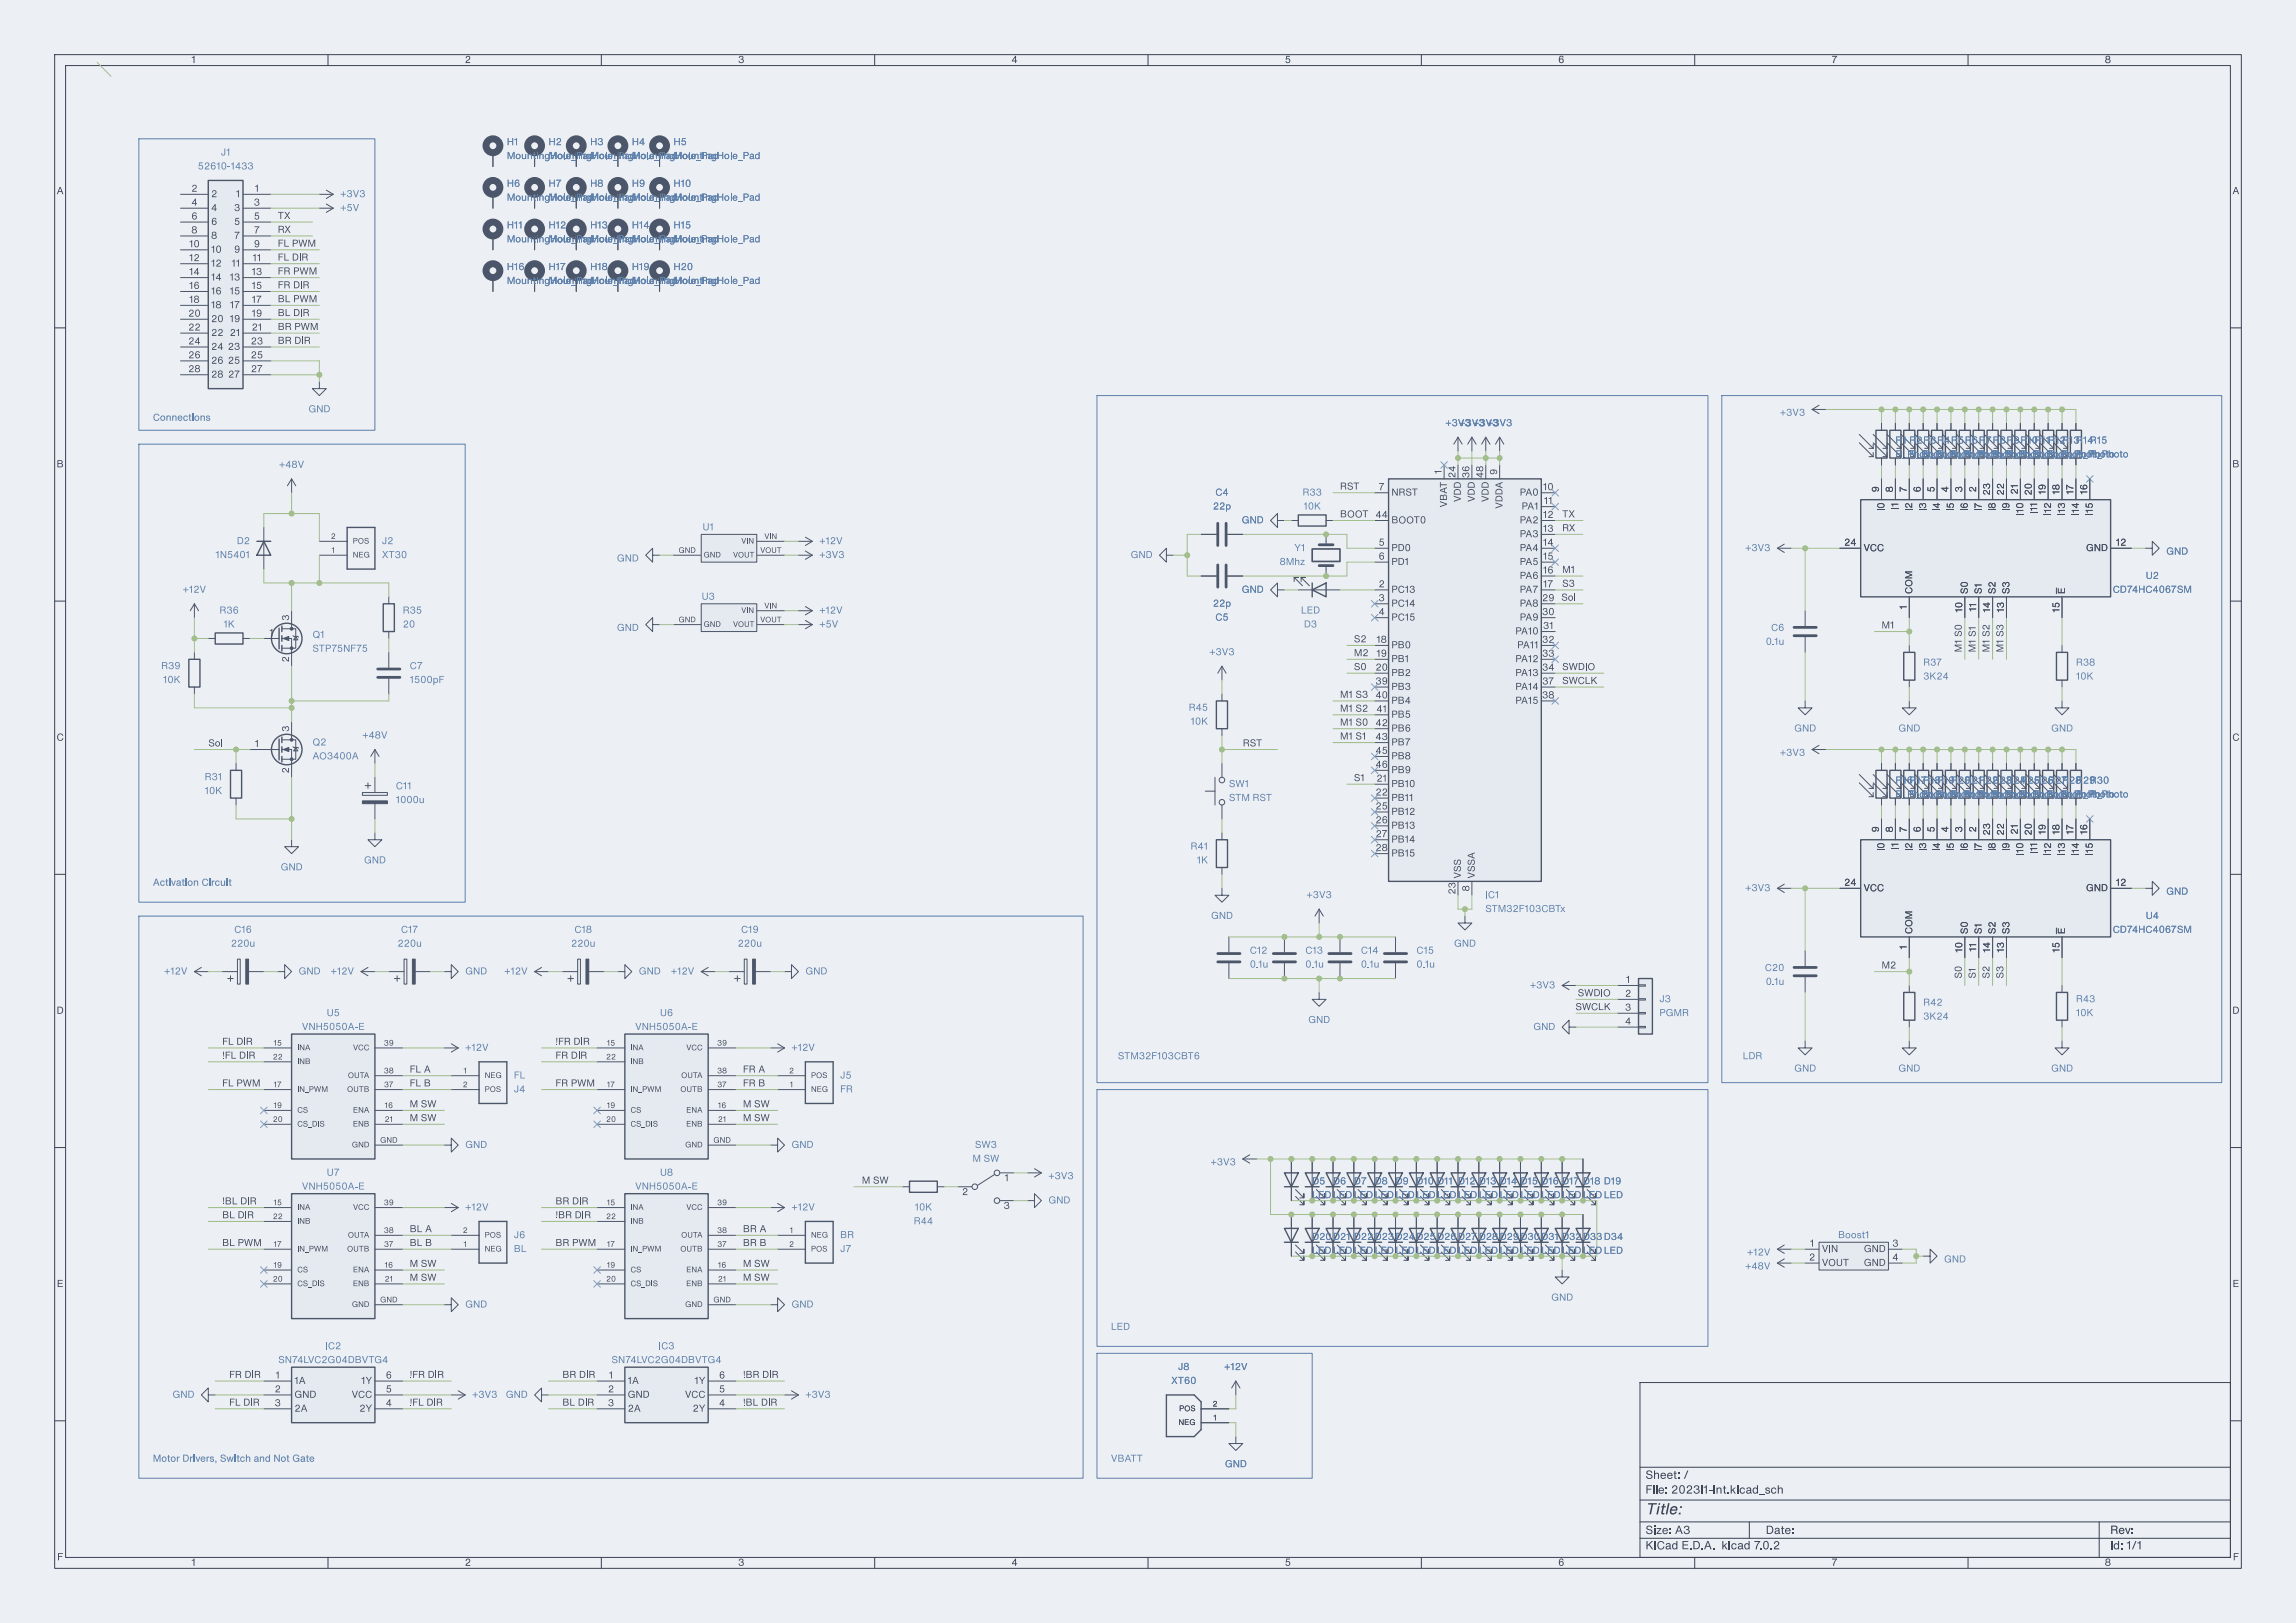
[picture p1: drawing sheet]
<svg xmlns="http://www.w3.org/2000/svg" width="420mm" height="297mm" viewBox="0 0 420 297" stroke-linecap="round" stroke-linejoin="round" font-family="sans-serif">
<defs><g id="words">
<text font-size="2.8" fill="#3b4252" x="301" y="277.8">Title:</text>
<g font-size="2.1" fill="#3b4252">
<text x="301" y="273.8">File: 2023l1-int.kicad_sch</text>
<text x="301" y="271.1">Sheet: /</text>
<text x="301" y="281.2">Size: A3</text>
<text x="323" y="281.2">Date:</text>
<text x="386" y="281.2">Rev:</text>
<text x="301" y="284">KiCad E.D.A. kicad 7.0.2</text>
<text x="386" y="284">Id: 1/1</text>
</g>
<g font-size="1.8" fill="#3b4252">
<text x="35" y="12">1</text>
<text x="85" y="12">2</text>
<text x="135" y="12">3</text>
<text x="185" y="12">4</text>
<text x="235" y="12">5</text>
<text x="285" y="12">6</text>
<text x="335" y="12">7</text>
<text x="385" y="12">8</text>
<text x="10.3" y="36">A</text>
<text x="408.3" y="36">A</text>
<text x="10.3" y="86">B</text>
<text x="408.3" y="86">B</text>
<text x="10.3" y="136">C</text>
<text x="408.3" y="136">C</text>
<text x="10.4" y="186">D</text>
<text x="408.3" y="186">D</text>
<text x="10.4" y="236">E</text>
<text x="408.4" y="236">E</text>
<text x="10.5" y="286">F</text>
<text x="35" y="287">1</text>
<text x="85" y="287">2</text>
<text x="135" y="287">3</text>
<text x="185" y="287">4</text>
<text x="235" y="287">5</text>
<text x="285" y="287">6</text>
<text x="335" y="287">7</text>
<text x="385" y="287">8</text>
<text x="408.4" y="286">F</text>
</g>
<g font-size="1.8" fill="#5e81ac">
<text x="40.4" y="28.9">J1</text>
<text x="92.7" y="27">H1</text>
<text x="92.7" y="29.5">MountingHole_PadMountingHole_PadMountingHole_Pad</text>
<text x="100.3" y="27">H2</text>
<text x="107.9" y="27">H3</text>
<text x="115.6" y="27">H4</text>
<text x="123.2" y="27">H5</text>
<text x="36.2" y="31.4">52610-1433</text>
<text x="92.7" y="34.6">H6</text>
<text x="100.3" y="34.6">H7</text>
<text x="107.9" y="34.6">H8</text>
<text x="115.6" y="34.6">H9</text>
<text x="123.2" y="34.6">H10</text>
<text x="62.2" y="36.5">+3V3</text>
<text x="62.2" y="39">+5V</text>
<text x="92.7" y="37.1">MountingHole_PadMountingHole_PadMountingHole_Pad</text>
<text x="92.7" y="42.2">H11</text>
<text x="100.3" y="42.2">H12</text>
<text x="107.9" y="42.2">H13</text>
<text x="115.6" y="42.2">H14</text>
<text x="123.2" y="42.2">H15</text>
<text x="92.7" y="49.8">H16</text>
<text x="92.7" y="52.4">MountingHole_PadMountingHole_PadMountingHole_Pad</text>
<text x="100.3" y="49.8">H17</text>
<text x="100.3" y="52.4">MountingHole_PadMountingHole_Pad</text>
<text x="107.9" y="49.8">H18</text>
<text x="115.6" y="49.8">H19</text>
<text x="123.2" y="49.8">H20</text>
<text x="27.9" y="77.2">Connections</text>
<text x="56.4" y="75.9">GND</text>
<text x="325.6" y="76.5">+3V3</text>
<text x="264.4" y="78.4">+3V3 +3V3</text>
<text x="346.7" y="81.6">R1R2R3R4R5R6R7R8R9R10R11R12R13R14R15</text>
<text x="51" y="86">+48V</text>
<text x="346.7" y="84.1">R_Photo</text>
<text x="349.2" y="84.1">R_Photo R_Photo</text>
<text x="351.8" y="84.1">R_Photo R_Photo R_Photo R_Photo R_Photo</text>
<text x="351.8" y="84.1">R_Photo</text>
<text x="369.6" y="84.1">R_Photo</text>
<text x="372.1" y="84.1">R_Photo</text>
<text x="374.6" y="84.1">R_Photo R_Photo</text>
<text x="221.8" y="93.7">22p</text>
<text x="222.3" y="91.1">C4</text>
<text x="238.3" y="91.1">R33</text>
<text x="238.4" y="93.7">10K</text>
<text x="43.3" y="100">D2</text>
<text x="69.8" y="100">J2</text>
<text x="128.5" y="97.5">U1</text>
<text x="149.9" y="100">+12V</text>
<text x="227.1" y="96.2">GND</text>
<text x="236.7" y="101.3">Y1</text>
<text x="319.2" y="101.3">+3V3</text>
<text x="396.2" y="101.9">GND</text>
<text x="39.4" y="102.5">1N5401</text>
<text x="69.8" y="102.5">XT30</text>
<text x="112.8" y="103.2">GND</text>
<text x="149.9" y="102.5">+3V3</text>
<text x="206.8" y="102.5">GND</text>
<text x="234.1" y="103.8">8Mhz</text>
<text x="392.5" y="106.4">U2</text>
<text x="33.4" y="108.9">+12V</text>
<text x="40.1" y="112.7">R36</text>
<text x="73.7" y="112.7">R35</text>
<text x="128.3" y="110.2">U3</text>
<text x="149.9" y="112.7">+12V</text>
<text x="221.8" y="111.4">22p</text>
<text x="222.3" y="114">C5</text>
<text x="227.1" y="108.9">GND</text>
<text x="238" y="112.7">LED</text>
<text x="386.5" y="108.9">CD74HC4067SM</text>
<text x="40.9" y="115.2">1K</text>
<text x="57.1" y="117.2">Q1</text>
<text x="57.1" y="119.7">STP75NF75</text>
<text x="73.7" y="115.2">20</text>
<text x="112.8" y="115.9">GND</text>
<text x="149.9" y="115.2">+5V</text>
<text x="238.5" y="115.2">D3</text>
<text x="323" y="118.4">0.1u</text>
<text x="324" y="115.9">C6</text>
<text x="29.5" y="122.9">R39</text>
<text x="29.8" y="125.4">10K</text>
<text x="74.9" y="122.9">C7</text>
<text x="74.9" y="125.4">1500pF</text>
<text x="221.2" y="120.3">+3V3</text>
<text x="351.8" y="122.2">R37</text>
<text x="351.8" y="124.8">3K24</text>
<text x="379.7" y="122.2">R38</text>
<text x="379.7" y="124.8">10K</text>
<text x="217.4" y="130.5">R45</text>
<text x="57.1" y="136.8">Q2</text>
<text x="66.3" y="135.6">+48V</text>
<text x="217.8" y="133">10K</text>
<text x="328.2" y="134.3">GND</text>
<text x="347.2" y="134.3">GND</text>
<text x="375.2" y="134.3">GND</text>
<text x="37.4" y="143.2">R31</text>
<text x="57.1" y="139.4">AO3400A</text>
<text x="325.6" y="138.7">+3V3</text>
<text x="346.7" y="143.8">R16R17R18R19R20R21R22R23R24R25R26R27R28R29R30</text>
<text x="37.4" y="145.7">10K</text>
<text x="72.4" y="144.8">C11</text>
<text x="72.4" y="147.4">1000u</text>
<text x="224.8" y="144.5">SW1</text>
<text x="224.8" y="147">STM RST</text>
<text x="346.7" y="146.4">R_Photo R_Photo</text>
<text x="359.4" y="146.4">R_Photo R_Photo R_Photo R_Photo</text>
<text x="217.8" y="155.9">R41</text>
<text x="51.3" y="159.7">GND</text>
<text x="66.6" y="158.4">GND</text>
<text x="218.9" y="158.4">1K</text>
<text x="27.9" y="162.3">Activation Circuit</text>
<text x="239" y="164.8">+3V3</text>
<text x="271.7" y="164.8">IC1</text>
<text x="271.7" y="167.3">STM32F103CBTx</text>
<text x="319.2" y="163.5">+3V3</text>
<text x="396.2" y="164.1">GND</text>
<text x="42.2" y="173.7">220u</text>
<text x="42.8" y="171.1">C16</text>
<text x="72.7" y="173.7">220u</text>
<text x="73.3" y="171.1">C17</text>
<text x="104.4" y="173.7">220u</text>
<text x="105.1" y="171.1">C18</text>
<text x="134.9" y="173.7">220u</text>
<text x="135.5" y="171.1">C19</text>
<text x="221.5" y="168.6">GND</text>
<text x="266" y="173.7">GND</text>
<text x="386.5" y="171.1">CD74HC4067SM</text>
<text x="392.5" y="168.6">U4</text>
<text x="30" y="178.7">+12V</text>
<text x="54.6" y="178.7">GND</text>
<text x="60.5" y="178.7">+12V</text>
<text x="85.1" y="178.7">GND</text>
<text x="92.2" y="178.7">+12V</text>
<text x="116.8" y="178.7">GND</text>
<text x="122.7" y="178.7">+12V</text>
<text x="147.3" y="178.7">GND</text>
<text x="228.6" y="174.9">C12</text>
<text x="228.6" y="177.5">0.1u</text>
<text x="238.8" y="174.9">C13</text>
<text x="238.8" y="177.5">0.1u</text>
<text x="248.9" y="174.9">C14</text>
<text x="248.9" y="177.5">0.1u</text>
<text x="259.1" y="174.9">C15</text>
<text x="259.1" y="177.5">0.1u</text>
<text x="322.8" y="178.1">C20</text>
<text x="279.9" y="181.3">+3V3</text>
<text x="303.5" y="183.8">J3</text>
<text x="323" y="180.7">0.1u</text>
<text x="351.8" y="184.5">R42</text>
<text x="379.7" y="183.8">R43</text>
<text x="55.2" y="188.9">VNH5050A-E</text>
<text x="59.8" y="186.4">U5</text>
<text x="116.2" y="188.9">VNH5050A-E</text>
<text x="120.7" y="186.4">U6</text>
<text x="239.3" y="187.6">GND</text>
<text x="280.5" y="188.9">GND</text>
<text x="303.5" y="186.4">PGMR</text>
<text x="351.8" y="187">3K24</text>
<text x="379.7" y="186.4">10K</text>
<text x="85.1" y="192.7">+12V</text>
<text x="94" y="197.8">FL</text>
<text x="144.8" y="192.7">+12V</text>
<text x="153.7" y="197.8">J5</text>
<text x="204.5" y="194.1">STM32F103CBT6</text>
<text x="318.8" y="194.1">LDR</text>
<text x="328.2" y="196.5">GND</text>
<text x="347.2" y="196.5">GND</text>
<text x="375.2" y="196.5">GND</text>
<text x="94" y="200.3">J4</text>
<text x="153.7" y="200.3">FR</text>
<text x="59.8" y="215.6">U7</text>
<text x="85.1" y="210.5">GND</text>
<text x="120.7" y="215.6">U8</text>
<text x="144.8" y="210.5">GND</text>
<text x="177.9" y="213">M SW</text>
<text x="178.3" y="210.5">SW3</text>
<text x="221.4" y="213.7">+3V3</text>
<text x="55.2" y="218.1">VNH5050A-E</text>
<text x="85.1" y="221.9">+12V</text>
<text x="116.2" y="218.1">VNH5050A-E</text>
<text x="144.8" y="221.9">+12V</text>
<text x="167.3" y="221.9">10K</text>
<text x="191.8" y="216.2">+3V3</text>
<text x="191.8" y="220.7">GND</text>
<text x="240" y="217.2">D5</text>
<text x="243.8" y="217.2">D6</text>
<text x="247.6" y="217.2">D7</text>
<text x="251.5" y="217.2">D8</text>
<text x="255.3" y="217.2">D9</text>
<text x="259.1" y="217.2">D10</text>
<text x="262.9" y="217.2">D11</text>
<text x="266.7" y="217.2">D12</text>
<text x="270.5" y="217.2">D13 D14 D15</text>
<text x="281.9" y="217.2">D16</text>
<text x="285.8" y="217.2">D17</text>
<text x="289.6" y="217.2">D18 D19</text>
<text x="94" y="227">J6</text>
<text x="153.7" y="227">BR</text>
<text x="167.1" y="224.5">R44</text>
<text x="240" y="227.3">D20</text>
<text x="243.8" y="227.3">D21</text>
<text x="247.6" y="227.3">D22</text>
<text x="251.5" y="227.3">D23 D24 D25</text>
<text x="262.9" y="227.3">D26</text>
<text x="266.7" y="227.3">D27</text>
<text x="270.5" y="227.3">D28 D29 D30</text>
<text x="281.9" y="227.3">D31</text>
<text x="285.8" y="227.3">D32</text>
<text x="289.6" y="227.3">D33 D34</text>
<text x="336.2" y="227">Boost1</text>
<text x="94" y="229.5">BL</text>
<text x="153.7" y="229.5">J7</text>
<text x="319.2" y="232.7">+48V</text>
<text x="319.6" y="230.2">+12V</text>
<text x="355.6" y="231.5">GND</text>
<text x="85.1" y="239.7">GND</text>
<text x="144.8" y="239.7">GND</text>
<text x="283.7" y="238.4">GND</text>
<text x="203.2" y="243.6">LED</text>
<text x="50.9" y="249.9">SN74LVC2G04DBVTG4</text>
<text x="59.5" y="247.3">IC2</text>
<text x="111.9" y="249.9">SN74LVC2G04DBVTG4</text>
<text x="120.5" y="247.3">IC3</text>
<text x="215.5" y="251.1">J8</text>
<text x="223.9" y="251.1">+12V</text>
<text x="31.6" y="256.2">GND</text>
<text x="86.4" y="256.2">+3V3</text>
<text x="92.5" y="256.2">GND</text>
<text x="147.3" y="256.2">+3V3</text>
<text x="214.2" y="253.7">XT60</text>
<text x="27.9" y="267.7">Motor Drivers,Switch and Not Gate</text>
<text x="203.2" y="267.7">VBATT</text>
<text x="224.1" y="268.9">GND</text>
</g>
<g font-size="1.8" fill="#4c566a">
<text x="100.3" y="29.5">MountingHole_PadMountingHole_Pad</text>
<text x="100.3" y="37.1">MountingHole_PadMountingHole_Pad</text>
<text x="92.7" y="44.8">MountingHole_PadMountingHole_PadMountingHole_Pad</text>
<text x="100.3" y="44.8">MountingHole_PadMountingHole_Pad</text>
</g>
<g font-size="1.8" fill="#434c5e">
<text x="35" y="35.3">2</text>
<text x="46.6" y="35.3">1</text>
<text x="35" y="37.8">4</text>
<text x="35" y="40.4">6</text>
<text x="38.6" y="36.5">2</text>
<text x="38.6" y="39">4</text>
<text x="38.6" y="41.6">6</text>
<text x="42.8" y="39">3</text>
<text x="42.8" y="41.6">5</text>
<text x="43.1" y="36.5">1</text>
<text x="46.4" y="37.8">3</text>
<text x="46.4" y="40.4">5</text>
<text x="50.8" y="40.3">TX</text>
<text x="34.6" y="45.5">10</text>
<text x="35" y="42.9">8</text>
<text x="38.6" y="46.7">10</text>
<text x="38.6" y="44.1">8</text>
<text x="42.8" y="44.1">7</text>
<text x="42.8" y="46.7">9</text>
<text x="46.4" y="42.9">7</text>
<text x="46.4" y="45.5">9</text>
<text x="50.8" y="45.4">FL PWM</text>
<text x="50.8" y="42.8">RX</text>
<text x="50.8" y="47.9">FL DIR</text>
<text x="34.6" y="48">12</text>
<text x="34.6" y="50.5">14</text>
<text x="34.6" y="53.1">16</text>
<text x="38.6" y="49.2">12</text>
<text x="38.6" y="51.7">14</text>
<text x="42" y="51.7">13</text>
<text x="42.3" y="49.2">11</text>
<text x="46" y="50.5">13</text>
<text x="46" y="53.1">15</text>
<text x="46.2" y="48">11</text>
<text x="50.8" y="53">FR DIR</text>
<text x="50.8" y="50.5">FR PWM</text>
<text x="34.4" y="58.2">20</text>
<text x="34.6" y="55.6">18</text>
<text x="38.6" y="54.3">16</text>
<text x="38.6" y="56.8">18</text>
<text x="38.6" y="59.4">20</text>
<text x="42" y="54.3">15</text>
<text x="42" y="59.4">19</text>
<text x="42" y="56.8">17</text>
<text x="46" y="58.2">19</text>
<text x="46" y="55.6">17</text>
<text x="50.8" y="58.1">BL DIR</text>
<text x="50.8" y="55.5">BL PWM</text>
<text x="34.4" y="60.7">22</text>
<text x="34.4" y="63.2">24</text>
<text x="34.4" y="65.8">26</text>
<text x="38.6" y="61.9">22</text>
<text x="38.6" y="64.4">24</text>
<text x="41.7" y="64.4">23</text>
<text x="42" y="61.9">21</text>
<text x="45.9" y="63.2">23</text>
<text x="45.9" y="65.8">25</text>
<text x="46" y="60.7">21</text>
<text x="50.8" y="63.2">BR DIR</text>
<text x="50.8" y="60.6">BR PWM</text>
<text x="34.4" y="68.3">28</text>
<text x="38.6" y="67">26</text>
<text x="38.6" y="69.5">28</text>
<text x="41.7" y="67">25</text>
<text x="41.7" y="69.5">27</text>
<text x="45.9" y="68.3">27</text>
<text x="245.1" y="89.8">RST</text>
<text x="252.2" y="89.9">7</text>
<text x="263.9" y="86.8" transform="rotate(-90 263.9 86.8)">1</text>
<text x="266.4" y="87.5" transform="rotate(-90 266.4 87.5)">24</text>
<text x="269" y="87.5" transform="rotate(-90 269 87.5)">36</text>
<text x="271.5" y="87.5" transform="rotate(-90 271.5 87.5)">48</text>
<text x="274.1" y="86.9" transform="rotate(-90 274.1 86.9)">9</text>
<text x="282.2" y="89.9">10</text>
<text x="245.1" y="94.9">BOOT</text>
<text x="251.6" y="95">44</text>
<text x="254.5" y="91.1">NRST</text>
<text x="265.1" y="92.9" transform="rotate(-90 265.1 92.9)">VBAT</text>
<text x="267.6" y="91.9" transform="rotate(-90 267.6 91.9)">VDD</text>
<text x="270.2" y="91.9" transform="rotate(-90 270.2 91.9)">VDD</text>
<text x="272.7" y="91.9" transform="rotate(-90 272.7 91.9)">VDD</text>
<text x="275.3" y="93.1" transform="rotate(-90 275.3 93.1)">VDDA</text>
<text x="278" y="91.1">PA0</text>
<text x="278.3" y="93.7">PA1</text>
<text x="282.2" y="95">12</text>
<text x="282.4" y="92.5">11</text>
<text x="285.8" y="94.9">TX</text>
<text x="343.9" y="90.1" transform="rotate(-90 343.9 90.1)">9</text>
<text x="345.1" y="93.6" transform="rotate(-90 345.1 93.6)">I0</text>
<text x="346.5" y="90.1" transform="rotate(-90 346.5 90.1)">8</text>
<text x="347.7" y="93.2" transform="rotate(-90 347.7 93.2)">I1</text>
<text x="349" y="90.1" transform="rotate(-90 349 90.1)">7</text>
<text x="350.2" y="93.6" transform="rotate(-90 350.2 93.6)">I2</text>
<text x="351.5" y="90.1" transform="rotate(-90 351.5 90.1)">6</text>
<text x="352.7" y="93.6" transform="rotate(-90 352.7 93.6)">I3</text>
<text x="354.1" y="90.1" transform="rotate(-90 354.1 90.1)">5</text>
<text x="355.3" y="93.6" transform="rotate(-90 355.3 93.6)">I4</text>
<text x="356.6" y="90.1" transform="rotate(-90 356.6 90.1)">4</text>
<text x="357.8" y="93.6" transform="rotate(-90 357.8 93.6)">I5</text>
<text x="359.2" y="90.1" transform="rotate(-90 359.2 90.1)">3</text>
<text x="360.4" y="93.6" transform="rotate(-90 360.4 93.6)">I6</text>
<text x="361.7" y="90.1" transform="rotate(-90 361.7 90.1)">2</text>
<text x="362.9" y="93.6" transform="rotate(-90 362.9 93.6)">I7</text>
<text x="364.2" y="90.7" transform="rotate(-90 364.2 90.7)">23</text>
<text x="365.4" y="93.6" transform="rotate(-90 365.4 93.6)">I8</text>
<text x="366.8" y="90.7" transform="rotate(-90 366.8 90.7)">22</text>
<text x="368" y="93.6" transform="rotate(-90 368 93.6)">I9</text>
<text x="369.3" y="90.5" transform="rotate(-90 369.3 90.5)">21</text>
<text x="370.5" y="94.4" transform="rotate(-90 370.5 94.4)">I10</text>
<text x="371.9" y="90.7" transform="rotate(-90 371.9 90.7)">20</text>
<text x="373.1" y="94" transform="rotate(-90 373.1 94)">I11</text>
<text x="374.4" y="90.5" transform="rotate(-90 374.4 90.5)">19</text>
<text x="375.6" y="94.4" transform="rotate(-90 375.6 94.4)">I12</text>
<text x="376.9" y="90.5" transform="rotate(-90 376.9 90.5)">18</text>
<text x="378.1" y="94.4" transform="rotate(-90 378.1 94.4)">I13</text>
<text x="379.5" y="90.5" transform="rotate(-90 379.5 90.5)">17</text>
<text x="380.7" y="94.4" transform="rotate(-90 380.7 94.4)">I14</text>
<text x="382" y="90.5" transform="rotate(-90 382 90.5)">16</text>
<text x="383.2" y="94.4" transform="rotate(-90 383.2 94.4)">I15</text>
<text x="252.2" y="100.1">5</text>
<text x="254.5" y="96.2">BOOT0</text>
<text x="254.5" y="101.3">PD0</text>
<text x="278" y="96.2">PA2</text>
<text x="278" y="98.7">PA3</text>
<text x="278" y="101.3">PA4</text>
<text x="282.2" y="97.5">13</text>
<text x="282.2" y="100.1">14</text>
<text x="285.8" y="97.4">RX</text>
<text x="337.3" y="100.1">24</text>
<text x="340.9" y="101.3">VCC</text>
<text x="381.6" y="101.3">GND</text>
<text x="387" y="100.1">12</text>
<text x="252.2" y="107.7">2</text>
<text x="252.2" y="102.6">6</text>
<text x="254.5" y="103.8">PD1</text>
<text x="278" y="103.8">PA5</text>
<text x="278" y="106.4">PA6</text>
<text x="282.2" y="102.6">15</text>
<text x="282.2" y="105.2">16</text>
<text x="282.3" y="107.7">17</text>
<text x="285.8" y="107.6">S3</text>
<text x="285.8" y="105.1">M1</text>
<text x="53.1" y="113.6" transform="rotate(-90 53.1 113.6)">3</text>
<text x="252.2" y="110.2">3</text>
<text x="252.2" y="112.8">4</text>
<text x="254.5" y="108.9">PC13</text>
<text x="254.5" y="111.4">PC14</text>
<text x="254.5" y="114">PC15</text>
<text x="278" y="108.9">PA7</text>
<text x="278" y="111.4">PA8</text>
<text x="278" y="114">PA9</text>
<text x="282.1" y="110.2">29</text>
<text x="282.1" y="112.8">30</text>
<text x="285.6" y="110.1">Sol</text>
<text x="349" y="111.5" transform="rotate(-90 349 111.5)">1</text>
<text x="350.2" y="108.7" transform="rotate(-90 350.2 108.7)">COM</text>
<text x="359.2" y="112.1" transform="rotate(-90 359.2 112.1)">10</text>
<text x="360.4" y="108.7" transform="rotate(-90 360.4 108.7)">S0</text>
<text x="361.7" y="111.9" transform="rotate(-90 361.7 111.9)">11</text>
<text x="362.9" y="108.7" transform="rotate(-90 362.9 108.7)">S1</text>
<text x="364.2" y="112.1" transform="rotate(-90 364.2 112.1)">14</text>
<text x="365.4" y="108.7" transform="rotate(-90 365.4 108.7)">S2</text>
<text x="366.8" y="112.1" transform="rotate(-90 366.8 112.1)">13</text>
<text x="368" y="108.7" transform="rotate(-90 368 108.7)">S3</text>
<text x="376.9" y="112.1" transform="rotate(-90 376.9 112.1)">15</text>
<text x="49.3" y="116.6">1</text>
<text x="247.6" y="117.8">S2</text>
<text x="251.8" y="117.9">18</text>
<text x="254.5" y="119.1">PB0</text>
<text x="277.2" y="116.5">PA10</text>
<text x="277.5" y="119.1">PA11</text>
<text x="282.1" y="117.9">32</text>
<text x="282.2" y="115.3">31</text>
<text x="344.2" y="115.2">M1</text>
<text x="359.1" y="119.4" transform="rotate(-90 359.1 119.4)">M1 S0</text>
<text x="361.6" y="119.4" transform="rotate(-90 361.6 119.4)">M1 S1</text>
<text x="364.1" y="119.4" transform="rotate(-90 364.1 119.4)">M1 S2</text>
<text x="366.7" y="119.4" transform="rotate(-90 366.7 119.4)">M1 S3</text>
<text x="53.1" y="121.2" transform="rotate(-90 53.1 121.2)">2</text>
<text x="247.6" y="122.8">S0</text>
<text x="247.6" y="120.3">M2</text>
<text x="251.6" y="122.9">20</text>
<text x="251.6" y="125.5">39</text>
<text x="251.8" y="120.4">19</text>
<text x="254.5" y="121.6">PB1</text>
<text x="254.5" y="124.1">PB2</text>
<text x="277.2" y="121.6">PA12</text>
<text x="277.2" y="124.1">PA13</text>
<text x="282.1" y="120.4">33</text>
<text x="282.1" y="122.9">34</text>
<text x="282.1" y="125.5">37</text>
<text x="285.8" y="125.4">SWCLK</text>
<text x="285.8" y="122.8">SWDIO</text>
<text x="245.1" y="130.5">M1 S2</text>
<text x="245.1" y="127.9">M1 S3</text>
<text x="251.6" y="128">40</text>
<text x="251.8" y="130.6">41</text>
<text x="254.5" y="126.7">PB3</text>
<text x="254.5" y="129.2">PB4</text>
<text x="254.5" y="131.8">PB5</text>
<text x="277.2" y="126.7">PA14</text>
<text x="277.2" y="129.2">PA15</text>
<text x="282.1" y="128">38</text>
<text x="38.1" y="136.8">Sol</text>
<text x="46.6" y="136.9">1</text>
<text x="53.1" y="133.9" transform="rotate(-90 53.1 133.9)">3</text>
<text x="227.3" y="136.8">RST</text>
<text x="245.1" y="135.5">M1 S1</text>
<text x="245.1" y="133">M1 S0</text>
<text x="251.6" y="133.1">42</text>
<text x="251.6" y="135.6">43</text>
<text x="254.5" y="134.3">PB6</text>
<text x="254.5" y="136.8">PB7</text>
<text x="53.1" y="141.5" transform="rotate(-90 53.1 141.5)">2</text>
<text x="247.6" y="143.2">S1</text>
<text x="251.6" y="138.2">45</text>
<text x="251.6" y="140.7">46</text>
<text x="251.8" y="143.3">21</text>
<text x="254.5" y="139.4">PB8</text>
<text x="254.5" y="141.9">PB9</text>
<text x="251.6" y="145.8">22</text>
<text x="251.6" y="148.3">25</text>
<text x="254.5" y="144.5">PB10</text>
<text x="254.5" y="147">PB11</text>
<text x="254.5" y="149.5">PB12</text>
<text x="251.6" y="150.9">26</text>
<text x="251.6" y="156">28</text>
<text x="251.6" y="153.4">27</text>
<text x="254.5" y="152.1">PB13</text>
<text x="254.5" y="154.6">PB14</text>
<text x="343.9" y="152.3" transform="rotate(-90 343.9 152.3)">9</text>
<text x="345.1" y="155.8" transform="rotate(-90 345.1 155.8)">I0</text>
<text x="346.5" y="152.3" transform="rotate(-90 346.5 152.3)">8</text>
<text x="347.7" y="155.4" transform="rotate(-90 347.7 155.4)">I1</text>
<text x="349" y="152.3" transform="rotate(-90 349 152.3)">7</text>
<text x="350.2" y="155.8" transform="rotate(-90 350.2 155.8)">I2</text>
<text x="351.5" y="152.3" transform="rotate(-90 351.5 152.3)">6</text>
<text x="352.7" y="155.8" transform="rotate(-90 352.7 155.8)">I3</text>
<text x="354.1" y="152.3" transform="rotate(-90 354.1 152.3)">5</text>
<text x="355.3" y="155.8" transform="rotate(-90 355.3 155.8)">I4</text>
<text x="356.6" y="152.3" transform="rotate(-90 356.6 152.3)">4</text>
<text x="357.8" y="155.8" transform="rotate(-90 357.8 155.8)">I5</text>
<text x="359.2" y="152.3" transform="rotate(-90 359.2 152.3)">3</text>
<text x="360.4" y="155.8" transform="rotate(-90 360.4 155.8)">I6</text>
<text x="361.7" y="152.3" transform="rotate(-90 361.7 152.3)">2</text>
<text x="362.9" y="155.8" transform="rotate(-90 362.9 155.8)">I7</text>
<text x="364.2" y="152.9" transform="rotate(-90 364.2 152.9)">23</text>
<text x="365.4" y="155.8" transform="rotate(-90 365.4 155.8)">I8</text>
<text x="366.8" y="152.9" transform="rotate(-90 366.8 152.9)">22</text>
<text x="368" y="155.8" transform="rotate(-90 368 155.8)">I9</text>
<text x="369.3" y="152.7" transform="rotate(-90 369.3 152.7)">21</text>
<text x="371.9" y="152.9" transform="rotate(-90 371.9 152.9)">20</text>
<text x="374.4" y="152.7" transform="rotate(-90 374.4 152.7)">19</text>
<text x="376.9" y="152.7" transform="rotate(-90 376.9 152.7)">18</text>
<text x="379.5" y="152.7" transform="rotate(-90 379.5 152.7)">17</text>
<text x="382" y="152.7" transform="rotate(-90 382 152.7)">16</text>
<text x="254.5" y="157.2">PB15</text>
<text x="267.6" y="160.8" transform="rotate(-90 267.6 160.8)">VSS</text>
<text x="270.2" y="160.8" transform="rotate(-90 270.2 160.8)">VSSA</text>
<text x="370.5" y="156.6" transform="rotate(-90 370.5 156.6)">I10</text>
<text x="373.1" y="156.2" transform="rotate(-90 373.1 156.2)">I11</text>
<text x="375.6" y="156.6" transform="rotate(-90 375.6 156.6)">I12</text>
<text x="378.1" y="156.6" transform="rotate(-90 378.1 156.6)">I13</text>
<text x="380.7" y="156.6" transform="rotate(-90 380.7 156.6)">I14</text>
<text x="383.2" y="156.6" transform="rotate(-90 383.2 156.6)">I15</text>
<text x="266.4" y="163.7" transform="rotate(-90 266.4 163.7)">23</text>
<text x="269" y="163.1" transform="rotate(-90 269 163.1)">8</text>
<text x="337.3" y="162.3">24</text>
<text x="340.9" y="163.5">VCC</text>
<text x="381.6" y="163.5">GND</text>
<text x="387" y="162.3">12</text>
<text x="349" y="173.8" transform="rotate(-90 349 173.8)">1</text>
<text x="350.2" y="170.9" transform="rotate(-90 350.2 170.9)">COM</text>
<text x="360.4" y="170.9" transform="rotate(-90 360.4 170.9)">S0</text>
<text x="362.9" y="170.9" transform="rotate(-90 362.9 170.9)">S1</text>
<text x="365.4" y="170.9" transform="rotate(-90 365.4 170.9)">S2</text>
<text x="368" y="170.9" transform="rotate(-90 368 170.9)">S3</text>
<text x="344.2" y="177.5">M2</text>
<text x="359.1" y="179.1" transform="rotate(-90 359.1 179.1)">S0</text>
<text x="359.2" y="174.3" transform="rotate(-90 359.2 174.3)">10</text>
<text x="361.6" y="179.1" transform="rotate(-90 361.6 179.1)">S1</text>
<text x="361.7" y="174.2" transform="rotate(-90 361.7 174.2)">11</text>
<text x="364.1" y="179.1" transform="rotate(-90 364.1 179.1)">S2</text>
<text x="364.2" y="174.3" transform="rotate(-90 364.2 174.3)">14</text>
<text x="366.7" y="179.1" transform="rotate(-90 366.7 179.1)">S3</text>
<text x="366.8" y="174.3" transform="rotate(-90 366.8 174.3)">13</text>
<text x="376.9" y="174.3" transform="rotate(-90 376.9 174.3)">15</text>
<text x="288.2" y="185.1">SWCLK</text>
<text x="288.6" y="182.5">SWDIO</text>
<text x="297.2" y="182.6">2</text>
<text x="297.2" y="185.2">3</text>
<text x="297.4" y="180.1">1</text>
<text x="40.6" y="191.4">FL DIR</text>
<text x="101.6" y="191.4">!FR DIR</text>
<text x="297.2" y="187.7">4</text>
<text x="40.6" y="194">!FL DIR</text>
<text x="74.9" y="196.5">FL A</text>
<text x="101.6" y="194">FR DIR</text>
<text x="135.9" y="196.5">FR A</text>
<text x="40.6" y="199">FL PWM</text>
<text x="74.9" y="202.9">M SW</text>
<text x="74.9" y="199">FL B</text>
<text x="101.6" y="199">FR PWM</text>
<text x="135.9" y="199">FR B</text>
<text x="135.9" y="202.9">M SW</text>
<text x="74.9" y="205.4">M SW</text>
<text x="135.9" y="205.4">M SW</text>
<text x="40.6" y="220.6">!BL DIR</text>
<text x="101.6" y="220.6">BR DIR</text>
<text x="157.6" y="216.8">M SW</text>
<text x="40.6" y="223.2">BL DIR</text>
<text x="74.9" y="225.7">BL A</text>
<text x="101.6" y="223.2">!BR DIR</text>
<text x="135.9" y="225.7">BR A</text>
<text x="40.6" y="228.3">BL PWM</text>
<text x="74.9" y="228.3">BL B</text>
<text x="74.9" y="232.1">M SW</text>
<text x="101.6" y="228.3">BR PWM</text>
<text x="135.9" y="232.1">M SW</text>
<text x="135.9" y="228.3">BR B</text>
<text x="330.9" y="230.9">2</text>
<text x="331.1" y="228.3">1</text>
<text x="333.2" y="229.5">VIN</text>
<text x="333.2" y="232.1">VOUT</text>
<text x="340.9" y="229.5">GND</text>
<text x="340.9" y="232.1">GND</text>
<text x="346.1" y="228.3">3</text>
<text x="346.1" y="230.9">4</text>
<text x="74.9" y="234.6">M SW</text>
<text x="135.9" y="234.6">M SW</text>
<text x="41.9" y="257.5">FL DIR</text>
<text x="41.9" y="252.4">FR DIR</text>
<text x="50.2" y="255">2</text>
<text x="50.2" y="257.6">3</text>
<text x="50.4" y="252.5">1</text>
<text x="53.8" y="253.7">1A</text>
<text x="53.8" y="256.2">GND</text>
<text x="64.3" y="256.2">VCC</text>
<text x="66.1" y="253.7">1Y</text>
<text x="70.6" y="257.6">4</text>
<text x="70.6" y="255">5</text>
<text x="70.6" y="252.5">6</text>
<text x="74.9" y="252.4">!FR DIR</text>
<text x="74.9" y="257.5">!FL DIR</text>
<text x="102.9" y="252.4">BR DIR</text>
<text x="102.9" y="257.5">BL DIR</text>
<text x="111.2" y="255">2</text>
<text x="111.2" y="257.6">3</text>
<text x="111.4" y="252.5">1</text>
<text x="114.8" y="253.7">1A</text>
<text x="114.8" y="256.2">GND</text>
<text x="125.3" y="256.2">VCC</text>
<text x="127" y="253.7">1Y</text>
<text x="131.5" y="257.6">4</text>
<text x="131.5" y="255">5</text>
<text x="131.5" y="252.5">6</text>
<text x="135.9" y="252.4">!BR DIR</text>
<text x="135.9" y="257.5">!BL DIR</text>
<text x="53.8" y="258.8">2A</text>
<text x="65.7" y="258.8">2Y</text>
<text x="114.8" y="258.8">2A</text>
<text x="126.7" y="258.8">2Y</text>
</g>
<g font-size="1.8" fill="#a3be8c">
<text x="240" y="219.7">LED</text>
<text x="243.8" y="219.7">LED</text>
<text x="247.6" y="219.7">LED</text>
<text x="251.5" y="219.7">LED LED LED</text>
<text x="262.9" y="219.7">LED</text>
<text x="266.7" y="219.7">LED</text>
<text x="270.5" y="219.7">LED LED LED</text>
<text x="281.9" y="219.7">LED</text>
<text x="285.8" y="219.7">LED</text>
<text x="289.6" y="219.7">LED LED</text>
<text x="240" y="229.9">LED</text>
<text x="243.8" y="229.9">LED</text>
<text x="247.6" y="229.9">LED</text>
<text x="251.5" y="229.9">LED LED LED</text>
<text x="262.9" y="229.9">LED</text>
<text x="266.7" y="229.9">LED</text>
<text x="270.5" y="229.9">LED LED LED</text>
<text x="281.9" y="229.9">LED</text>
<text x="285.8" y="229.9">LED</text>
<text x="289.6" y="229.9">LED LED</text>
</g>
<g font-size="1.4" fill="#434c5e">
<text x="60.5" y="98.8">2</text>
<text x="60.6" y="101.3">1</text>
<text x="64.5" y="99.8">POS</text>
<text x="124.1" y="101.3">GND</text>
<text x="135.6" y="99.8">VIN</text>
<text x="139" y="101.3">VOUT</text>
<text x="139.8" y="98.8">VIN</text>
<text x="64.5" y="102.4">NEG</text>
<text x="128.7" y="102.3">GND</text>
<text x="134.1" y="102.3">VOUT</text>
<text x="135.6" y="112.5">VIN</text>
<text x="139.8" y="111.5">VIN</text>
<text x="124.1" y="114">GND</text>
<text x="128.7" y="115">GND</text>
<text x="134.1" y="115">VOUT</text>
<text x="139" y="114">VOUT</text>
<text x="50" y="191.5">15</text>
<text x="70.2" y="191.5">39</text>
<text x="111" y="191.5">15</text>
<text x="131.2" y="191.5">39</text>
<text x="49.9" y="194.1">22</text>
<text x="54.4" y="192.5">INA</text>
<text x="54.4" y="195.1">INB</text>
<text x="63.6" y="197.6">OUTA</text>
<text x="64.6" y="192.5">VCC</text>
<text x="70.2" y="196.6">38</text>
<text x="84.8" y="196.6">1</text>
<text x="88.6" y="197.6">NEG</text>
<text x="110.8" y="194.1">22</text>
<text x="115.3" y="192.5">INA</text>
<text x="115.3" y="195.1">INB</text>
<text x="124.6" y="197.6">OUTA</text>
<text x="125.5" y="192.5">VCC</text>
<text x="131.2" y="196.6">38</text>
<text x="144.3" y="196.6">2</text>
<text x="148.3" y="197.6">POS</text>
<text x="50" y="202.9">19</text>
<text x="50" y="199.1">17</text>
<text x="54.4" y="200.1">IN_PWM</text>
<text x="54.4" y="204">CS</text>
<text x="63.5" y="200.1">OUTB</text>
<text x="64.6" y="204">ENA</text>
<text x="70.2" y="199.1">37</text>
<text x="70.3" y="202.9">16</text>
<text x="84.6" y="199.1">2</text>
<text x="88.6" y="200.1">POS</text>
<text x="111" y="202.9">19</text>
<text x="111" y="199.1">17</text>
<text x="115.3" y="200.1">IN_PWM</text>
<text x="115.3" y="204">CS</text>
<text x="124.4" y="200.1">OUTB</text>
<text x="125.5" y="204">ENA</text>
<text x="131.2" y="199.1">37</text>
<text x="131.3" y="202.9">16</text>
<text x="144.5" y="199.1">1</text>
<text x="148.3" y="200.1">NEG</text>
<text x="49.9" y="205.5">20</text>
<text x="54.4" y="206.5">CS_DIS</text>
<text x="64.5" y="206.5">ENB</text>
<text x="69.5" y="209.3">GND</text>
<text x="70.3" y="205.5">21</text>
<text x="110.8" y="205.5">20</text>
<text x="115.3" y="206.5">CS_DIS</text>
<text x="125.5" y="206.5">ENB</text>
<text x="130.5" y="209.3">GND</text>
<text x="131.3" y="205.5">21</text>
<text x="64.4" y="210.3">GND</text>
<text x="125.3" y="210.3">GND</text>
<text x="50" y="220.7">15</text>
<text x="54.4" y="221.7">INA</text>
<text x="64.6" y="221.7">VCC</text>
<text x="70.2" y="220.7">39</text>
<text x="111" y="220.7">15</text>
<text x="115.3" y="221.7">INA</text>
<text x="125.5" y="221.7">VCC</text>
<text x="131.2" y="220.7">39</text>
<text x="49.9" y="223.3">22</text>
<text x="54.4" y="224.3">INB</text>
<text x="63.6" y="226.8">OUTA</text>
<text x="70.2" y="225.8">38</text>
<text x="84.6" y="225.8">2</text>
<text x="88.6" y="226.8">POS</text>
<text x="110.8" y="223.3">22</text>
<text x="115.3" y="224.3">INB</text>
<text x="124.6" y="226.8">OUTA</text>
<text x="131.2" y="225.8">38</text>
<text x="144.5" y="225.8">1</text>
<text x="148.3" y="226.8">NEG</text>
<text x="50" y="232.2">19</text>
<text x="50" y="228.3">17</text>
<text x="54.4" y="229.4">IN_PWM</text>
<text x="54.4" y="233.2">CS</text>
<text x="63.5" y="229.4">OUTB</text>
<text x="64.6" y="233.2">ENA</text>
<text x="70.2" y="228.3">37</text>
<text x="70.3" y="232.2">16</text>
<text x="84.8" y="228.3">1</text>
<text x="88.6" y="229.4">NEG</text>
<text x="111" y="232.2">19</text>
<text x="111" y="228.3">17</text>
<text x="115.3" y="229.4">IN_PWM</text>
<text x="115.3" y="233.2">CS</text>
<text x="124.4" y="229.4">OUTB</text>
<text x="125.5" y="233.2">ENA</text>
<text x="131.2" y="228.3">37</text>
<text x="131.3" y="232.2">16</text>
<text x="144.3" y="228.3">2</text>
<text x="148.3" y="229.4">POS</text>
<text x="49.9" y="234.7">20</text>
<text x="54.4" y="235.7">CS_DIS</text>
<text x="64.4" y="239.5">GND</text>
<text x="64.5" y="235.7">ENB</text>
<text x="69.5" y="238.5">GND</text>
<text x="70.3" y="234.7">21</text>
<text x="110.8" y="234.7">20</text>
<text x="115.3" y="235.7">CS_DIS</text>
<text x="125.3" y="239.5">GND</text>
<text x="125.5" y="235.7">ENB</text>
<text x="130.5" y="238.5">GND</text>
<text x="131.3" y="234.7">21</text>
<text x="221.8" y="257.6">2</text>
<text x="215.6" y="261.1">NEG</text>
<text x="215.7" y="258.6">POS</text>
<text x="221.9" y="260.1">1</text>
</g>
</g></defs>
<path d="M0 0h420v297h-420z" fill="#eceff4" stroke="#eceff4" stroke-width=".18"/>
<g fill="none" stroke="#3b4252" stroke-width=".18">
<path d="M10 10h400v277h-400zM12 12h396v273h-396zM60 10v2M110 10v2M160 10v2M210 10v2M260 10v2M310 10v2M360 10v2M10 60h2M408 60h2M10 110h2"/>
<path d="M408 110h2M10 160h2M408 160h2M10 210h2M408 210h2M10 260h2M300 253h108v32h-108zM408 260h2M300 278.5h108M300 274.5h108M60 285v2M110 285v2"/>
<path d="M160 285v2M210 285v2M260 285v2M300 281.5h108M310 285v2M360 285v2"/>
</g>
<path d="M325.2 271.8h.2v.6l.3-.2 .4 .1v1h-.2v-.8l-.2-.1-.3 .1v.8h-.2z" fill="#3b4252"/>
<path d="M300 268.5h108M320 278.5v3M384 278.5v6.5" fill="none" stroke="#3b4252" stroke-width=".18"/>
<path d="M114.3 250.2h15.2v10.1h-15.2z" fill="#e5e9f0" stroke="#e5e9f0" stroke-width=".18"/>
<path d="M114.3 250.2h15.2v10.1h-15.2z" fill="none" stroke="#4c566a" stroke-width=".25"/>
<path d="M109.2 252.7h5.1M109.2 255.3h5.1M109.2 257.8h5.1M129.5 252.7h5.1M129.5 255.3h5.1M129.5 257.8h5.1" fill="none" stroke="#4c566a" stroke-width=".18"/>
<path d="M131.6 248.2h.1v.8h.2v.1h-.2v.3h-.2v-.3h-.6v-.1h.6v-.5l-.4 .5h-.2z" fill="#5e81ac"/>
<path d="M350.8 78.7h2v5.1h-2zM353.3 78.7h2v5.1h-2zM343.2 141h2v5.1h-2zM250.2 224.8h2.5l-1.2 2.5zM250.2 227.3h2.5M254 224.8h2.5l-1.2 2.5zM257.8 224.8h2.5l-1.2 2.5zM261.6 224.8h2.6l-1.3 2.5zM261.6 227.3h2.6" fill="none" stroke="#4c566a" stroke-width=".25"/>
<g fill="none" stroke="#4c566a" stroke-width=".18">
<path d="M347.7 79.5l2.6 2.5M350.3 79.5l2.5 2.5M351.8 77.5v1.2M354.3 77.5v1.2M274.3 80l-.7 1.3M274.3 80v2.6M274.3 80l.8 1.3M347.7 81l2.6 2.6M350.3 81l2.5 2.6M351.8 83.8v1.3M354.3 83.8v1.3M119.4 114.3v-1.3l-1.3 1.3 1.3 1.3v-1.3h1.2"/>
<path d="M119.4 101.6v-1.3l-1.3 1.3 1.3 1.3v-1.3h1.2M123.2 114.3h5M128.3 110.5h10.1v5.1h-10.1zM138.4 111.8h5.1M138.5 114.3h5M344.2 139.7v1.3M340.1 143.3l2.5 2.5M340.1 141.7l2.5 2.6M341.9 145.8h.7M341.9 144.3h.7M342.6 143.5v.8M342.6 145v.8"/>
<path d="M344.2 146.1v1.2M128.3 177.8h2.5M128.3 177.8l1.2 .8M129.5 177l-1.2 .8M133.3 177.8h2.8M134.4 179.1h1M134.9 178.6v1M136.1 175.5h.6v4.6h-.6zM138.2 177.8h2.8M143.5 177.8h1.3v-1.3l1.2 1.3-1.2 1.3v-1.3M287 188v1.2l-1.3-1.2 1.3-1.3v1.3h1.3M251.5 222.2v7.7"/>
<path d="M252.2 229.1l1.5 1.5v-.7v.7h-.7M252.2 227.8l1.5 1.6v-.8v.8h-.7M255.3 222.2v7.7M256 229.1l1.6 1.5v-.7v.7h-.8M256 227.8l1.6 1.6v-.8v.8h-.8M259.1 222.2v7.7M259.8 229.1l1.6 1.5v-.7v.7h-.8M259.8 227.8l1.6 1.6v-.8v.8h-.8M262.9 222.2v7.7M263.7 229.1l1.5 1.5v-.7v.7h-.8M263.7 227.8l1.5 1.6v-.8v.8h-.8"/>
</g>
<path d="M137.7 175.5h.5v4.6h-.5z" fill="#4c566a" stroke="#4c566a" stroke-width=".18"/>
<path d="M128.3 110.5h10.1v5.1h-10.1z" fill="#e5e9f0" stroke="#e5e9f0" stroke-width=".18"/>
<g fill="#5e81ac">
<path d="M274.3 76.7h.2l.4 1.1 .4-1.1h.1l-.4 1.3h-.2z"/>
<path d="M275.7 76.8l.4-.1 .3 .2v.2l-.1 .2 .2 .1v.3l-.2 .3h-.4l-.3-.2v-.2h.2l.2 .3 .4-.2-.1-.3h-.3v-.2h.3v-.3h-.4l-.1 .2h-.2z"/>
</g>
<g fill="none" stroke="#4c566a" stroke-width=".18">
<path d="M370.6 79.5l2.5 2.5M373.1 79.5l2.6 2.5M374.6 77.5v1.2M377.2 77.5v1.2M128.3 97.8h10.1v5.1h-10.1zM138.4 99.1h5.1M219.7 97.8h2.8M224.5 97.8h2.8M251.5 90.2h2.5M264.2 85.1v2.5M266.7 80l-.8 1.3M266.7 80v2.6"/>
<path d="M266.7 80l.8 1.3M269.2 80l-.7 1.3M269.2 80v2.6M269.2 80l.8 1.3M271.8 80l-.8 1.3M271.8 80v2.6M271.8 80l.7 1.3M274.3 85.1v2.5M281.9 92.7h2.6M370.6 81l2.5 2.6M373.1 81l2.6 2.6M374.6 83.8v1.3"/>
<path d="M377.2 83.8v1.3M123.2 101.6h5M138.5 101.6h5M146 111.8h2.6M147.3 111l1.3 .8M148.6 111.8l-1.3 .7M213.4 101.6v-1.3l-1.3 1.3 1.3 1.3v-1.3h1.2M219.7 105.4h2.8M224.5 105.4h2.8M251.5 108h2.5M251.5 110.5h2.5M251.5 113h2.5"/>
<path d="M251.5 100.3h2.5M251.5 102.9h2.5M281.9 115.6h2.6M223.5 121.9l-.7 1.3M223.5 121.9v2.6M223.5 127v1.3M223.5 133.4v1.2M223.5 139.7v2.5M223.5 121.9l.8 1.3M251.5 130.8h2.5M220.5 144.8h1.7M222.2 142.2v5.1"/>
<path d="M223.5 147.3v2.6M223.5 152.4v1.3M223.5 158.8v1.2M251.5 143.5h2.5M223.5 162.6v1.2h1.3l-1.3 1.3-1.3-1.3h1.3M241.3 166.4l-.8 1.2M241.3 166.4v2.5M241.3 166.4l.8 1.2M268 167.6v1.3h1.2l-1.2 1.3-1.3-1.3h1.3M269.2 161.3v2.5M182 214.9l-3.2 2M182.9 214.6h2.5"/>
<circle cx="223.5" cy="142.7" r=".51"/>
<circle cx="223.5" cy="146.8" r=".51"/>
<circle cx="178.3" cy="217.2" r=".51"/>
<circle cx="182.4" cy="219.7" r=".51"/>
<circle cx="182.4" cy="214.6" r=".51"/>
</g>
<g fill="#e5e9f0" stroke="#e5e9f0" stroke-width=".18">
<path d="M254 87.6h27.9v73.7h-27.9z"/>
<path d="M128.3 97.8h10.1v5.1h-10.1z"/>
</g>
<path d="M373.6 78.7h2.1v5.1h-2.1zM376.2 78.7h2v5.1h-2zM254 87.6h27.9v73.7h-27.9zM222.5 128.3h2v5.1h-2zM222.5 153.7h2v5.1h-2z" fill="none" stroke="#4c566a" stroke-width=".25"/>
<path d="M222.8 95.8v4M224.3 95.8v4M222.8 103.4v4M224.3 103.4v4" fill="none" stroke="#4c566a" stroke-width=".51"/>
<path d="M183.8 215.1l.5-.2v1.3h-.2v-1h-.3z" fill="#434c5e"/>
<path d="M175.3 217.2h2.5" fill="none" stroke="#4c566a" stroke-width=".18"/>
<path d="M176.3 217.5l.3-.1 .3 .2v.4l-.6 .5h.7v.2h-.9l.1-.3 .6-.6-.1-.2-.2-.1-.2 .3h-.2z" fill="#434c5e"/>
<path d="M182.9 219.7h2.5" fill="none" stroke="#4c566a" stroke-width=".18"/>
<path d="M183.8 220.1l.4-.2 .3 .2v.3l-.1 .1 .2 .2v.2l-.2 .3h-.4l-.3-.2v-.2h.1l.3 .3h.2l.2-.2-.1-.2-.3-.1v-.1l.3-.1v-.2l-.4-.1-.1 .2h-.2z" fill="#434c5e"/>
<path d="M253.2 176h4.1M253.2 174.5h4.1" fill="none" stroke="#4c566a" stroke-width=".51"/>
<g fill="none" stroke="#4c566a" stroke-width=".18">
<path d="M368 79.5l2.6 2.5M372.1 77.5v1.2M326.4 99.6l-1.3 .7M368 81l2.6 2.6M372.1 83.8v1.3M325.1 100.3l1.3 .8M325.1 100.3h2.6M255.3 171.5v2.7M255.3 176.3v2.8M349.2 171.5v3.8M359.4 171.5v3.8M361.9 171.5v3.8"/>
<path d="M364.5 171.5v3.8M367 171.5v3.8M377.2 171.5v3.8M386.1 162.6h3.8M188 219.7h1.2v-1.3l1.3 1.3-1.3 1.3v-1.3M188 214.6h2.5M189.2 213.9l1.3 .7M190.5 214.6l-1.3 .8"/>
</g>
<path d="M371.1 78.7h2v5.1h-2zM340.4 153.7h45.7v17.8h-45.7z" fill="none" stroke="#4c566a" stroke-width=".25"/>
<path d="M340.4 153.7h45.7v17.8h-45.7z" fill="#e5e9f0" stroke="#e5e9f0" stroke-width=".18"/>
<g fill="#434c5e">
<path d="M376.4 169.9h.2v.7h.4v-.7h.1v.7h.5v-.7h.1v.9h-1.3z"/>
<path d="M376.1 169.8h.1v1.1z"/>
</g>
<g fill="none" stroke="#4c566a" stroke-width=".18">
<path d="M344.2 149.9v3.8M346.7 149.9v3.8M349.2 149.9v3.8M351.8 149.9v3.8M354.3 149.9v3.8M356.9 149.9v3.8M359.4 149.9v3.8M361.9 149.9v3.8M364.5 149.9v3.8M367 149.9v3.8M369.6 149.9v3.8M372.1 149.9v3.8"/>
<path d="M374.6 149.9v3.8M377.2 149.9v3.8M379.7 149.9v3.8M382.3 149.9v3.8M336.5 162.6h3.9"/>
</g>
<path d="M399.5 169.4h.3l.4 1.1 .4-1.1h.2v1.3h-.2v-1.1l-.3 1.1h-.2l-.4-1.1v1.1h-.2z" fill="#5e81ac"/>
<g fill="none" stroke="#4c566a" stroke-width=".25">
<path d="M343.2 78.7h2v5.1h-2zM348.2 78.7h2.1v5.1h-2.1zM358.4 78.7h2v5.1h-2zM360.9 78.7h2.1v5.1h-2.1zM363.5 78.7h2v5.1h-2zM366 78.7h2v5.1h-2zM378.7 78.7h2v5.1h-2zM114.3 189.2h15.2v22.9h-15.2zM234.9 214.6h2.6l-1.3 2.6zM234.9 217.2h2.6M238.8 214.6h2.5l-1.3 2.6zM238.8 217.2h2.5"/>
<path d="M269.2 214.6h2.6l-1.3 2.6zM269.2 217.2h2.6M234.9 224.8h2.6l-1.3 2.5zM234.9 227.3h2.6M238.8 224.8h2.5l-1.3 2.5zM238.8 227.3h2.5M280.7 224.8h2.5l-1.3 2.5zM280.7 227.3h2.5"/>
</g>
<g fill="none" stroke="#4c566a" stroke-width=".18">
<path d="M340.1 79.5l2.5 2.5M344.2 77.5v1.2M345.2 79.5l2.5 2.5M349.2 77.5v1.2M355.3 79.5l2.6 2.5M357.9 79.5l2.5 2.5M359.4 77.5v1.2M360.4 79.5l2.6 2.5M361.9 77.5v1.2M363 79.5l2.5 2.5M364.5 77.5v1.2M367 77.5v1.2"/>
<path d="M375.7 79.5l2.5 2.5M379.7 77.5v1.2M340.1 81l2.5 2.6M341.9 83.6h.7M341.9 82h.7M342.6 81.3v.7M342.6 82.8v.8M344.2 83.8v1.3M345.2 81l2.5 2.6M349.2 83.8v1.3M355.3 81l2.6 2.6M357.9 81l2.5 2.6"/>
<path d="M359.4 83.8v1.3M360.4 81l2.6 2.6M361.9 83.8v1.3M363 81l2.5 2.6M364.5 83.8v1.3M367 83.8v1.3M375.7 81l2.5 2.6M379.7 83.8v1.3M146 114.3h2.6M147.3 113.5l1.3 .8M148.6 114.3l-1.3 .8M392.4 100.3h1.3v-1.2l1.3 1.2-1.3 1.3v-1.3"/>
<path d="M109.2 191.8h5.1M109.2 199.4h5.1M109.2 194.3h5.1M129.5 191.8h5.1M129.5 199.4h5.1M129.5 196.9h5.1M109.2 203.2h5.1M109.2 205.7h5.1M129.5 203.2h5.1M129.5 205.7h5.1M129.5 209.6h5.1M227.3 212.1l1.3 .8"/>
<path d="M227.3 212.1h2.6M228.6 211.3l-1.3 .8M236.2 212.1v7.6M237 218.9l1.5 1.6v-.8v.8h-.8M237 217.7l1.5 1.5v-.8v.8h-.8M240 212.1v7.6M240.8 218.9l1.5 1.6v-.8v.8h-.7M240.8 217.7l1.5 1.5v-.8v.8h-.7M270.5 212.1v7.6M271.3 218.9l1.5 1.6v-.8v.8h-.8M271.3 217.7l1.5 1.5v-.8v.8h-.8M236.2 222.2v7.7"/>
<path d="M237 229.1l1.5 1.5v-.7v.7h-.8M237 227.8l1.5 1.6v-.8v.8h-.8M240 222.2v7.7M240.8 229.1l1.5 1.5v-.7v.7h-.7M240.8 227.8l1.5 1.6v-.8v.8h-.7M281.9 222.2v7.7M282.7 229.1l1.5 1.5v-.7v.7h-.7M282.7 227.8l1.5 1.6v-.8v.8h-.7"/>
</g>
<path d="M114.3 189.2h15.2v22.9h-15.2z" fill="#e5e9f0" stroke="#e5e9f0" stroke-width=".18"/>
<path d="M126.6 187.2h.9v.1h-.7v.4h.7v.2h-.7v.4h.8v.2h-1z" fill="#5e81ac"/>
<path d="M328.2 114.8h4M328.2 116.3h4" fill="none" stroke="#4c566a" stroke-width=".51"/>
<g fill="none" stroke="#4c566a" stroke-width=".18">
<path d="M352.8 79.5l2.5 2.5M356.9 77.5v1.2M146 99.1h2.6M147.3 98.3l1.3 .8M148.6 99.1l-1.3 .7M352.8 81l2.5 2.6M356.9 83.8v1.3M146 101.6h2.6M147.3 100.8l1.3 .8M148.6 101.6l-1.3 .8M330.2 111.8v2.8M330.2 116.6v2.8"/>
<path d="M349.2 109.2v3.8M349.2 118.1v1.3M359.4 109.2v3.8M361.9 109.2v3.8M364.5 109.2v3.8M367 109.2v3.8M377.2 109.2v3.8M377.2 118.1v1.3M386.1 100.3h3.8M349.2 124.5v1.2M377.2 128.3v1.2h1.3l-1.3 1.3-1.3-1.3h1.3M377.2 124.5v1.2"/>
<path d="M102.9 177.8h2.8M103.9 179.1h1M104.4 178.6v1M105.7 175.5h.5v4.6h-.5zM107.7 177.8h2.8M113 177.8h1.3v-1.3l1.3 1.3-1.3 1.3v-1.3M392.4 162.6h1.3v-1.3l1.3 1.3-1.3 1.2v-1.2M141 191.8h2.5M142.2 199.4h5.1M142.2 196.9h5.1M142.2 191l1.3 .8M143.5 191.8l-1.3 .7"/>
<path d="M377.2 190.5v1.3h1.3l-1.3 1.2-1.3-1.2h1.3M141 209.6h1.2v-1.3l1.3 1.3-1.3 1.2v-1.2M165.1 217.2h1.3M171.4 217.2h1.3M243.8 212.1v7.6M244.6 218.9l1.5 1.6v-.8v.8h-.7M244.6 217.7l1.5 1.5v-.8v.8h-.7M247.6 212.1v7.6M248.4 218.9l1.5 1.6v-.8v.8h-.7M248.4 217.7l1.5 1.5v-.8v.8h-.7M251.5 212.1v7.6M252.2 218.9l1.5 1.6v-.8v.8h-.7"/>
<path d="M252.2 217.7l1.5 1.5v-.8v.8h-.7M255.3 212.1v7.6M256 218.9l1.6 1.6v-.8v.8h-.8M256 217.7l1.6 1.5v-.8v.8h-.8M259.1 212.1v7.6M259.8 218.9l1.6 1.6v-.8v.8h-.8M259.8 217.7l1.6 1.5v-.8v.8h-.8M262.9 212.1v7.6M263.7 218.9l1.5 1.6v-.8v.8h-.8M263.7 217.7l1.5 1.5v-.8v.8h-.8M266.7 212.1v7.6M267.5 218.9l1.5 1.6v-.8v.8h-.8"/>
<path d="M267.5 217.7l1.5 1.5v-.8v.8h-.8M274.3 212.1v7.6M275.1 218.9l1.5 1.6v-.8v.8h-.8M275.1 217.7l1.5 1.5v-.8v.8h-.8M278.1 212.1v7.6M278.9 218.9l1.5 1.6v-.8v.8h-.7M278.9 217.7l1.5 1.5v-.8v.8h-.7M281.9 212.1v7.6M282.7 218.9l1.5 1.6v-.8v.8h-.7M282.7 217.7l1.5 1.5v-.8v.8h-.7M141 238.8h1.2v-1.3l1.3 1.3-1.3 1.2v-1.2M141 221h2.5"/>
<path d="M142.2 226.1h5.1M142.2 228.6h5.1M142.2 220.2l1.3 .8M143.5 221l-1.3 .7M243.8 222.2v7.7M244.6 229.1l1.5 1.5v-.7v.7h-.7M244.6 227.8l1.5 1.6v-.8v.8h-.7M247.6 222.2v7.7M248.4 229.1l1.5 1.5v-.7v.7h-.7M248.4 227.8l1.5 1.6v-.8v.8h-.7M266.7 222.2v7.7M267.5 229.1l1.5 1.5v-.7v.7h-.8"/>
<path d="M267.5 227.8l1.5 1.6v-.8v.8h-.8M270.5 222.2v7.7M271.3 229.1l1.5 1.5v-.7v.7h-.8M271.3 227.8l1.5 1.6v-.8v.8h-.8M274.3 222.2v7.7M275.1 229.1l1.5 1.5v-.7v.7h-.8M275.1 227.8l1.5 1.6v-.8v.8h-.8M278.1 222.2v7.7M278.9 229.1l1.5 1.5v-.7v.7h-.7M278.9 227.8l1.5 1.6v-.8v.8h-.7M143.5 255.3h2.5M144.8 254.5l1.2 .8"/>
<path d="M146 255.3l-1.2 .7M219.7 257.8h5.1M226.1 252.7l-.8 1.3M226.1 252.7v2.6M226.1 252.7l.7 1.3M219.7 260.3h5.1M226.1 262.9v1.3h1.2l-1.2 1.2-1.3-1.2h1.3"/>
</g>
<g fill="none" stroke="#4c566a" stroke-width=".25">
<path d="M355.9 78.7h2v5.1h-2zM340.4 91.4h45.7v17.8h-45.7zM348.2 119.4h2.1v5.1h-2.1zM376.2 119.4h2v5.1h-2zM147.3 194.3h5.1v7.6h-5.1zM166.4 216.2h5v2h-5zM242.6 214.6h2.5l-1.3 2.6zM242.6 217.2h2.5M246.4 214.6h2.5l-1.3 2.6zM246.4 217.2h2.5M250.2 214.6h2.5l-1.2 2.6zM250.2 217.2h2.5"/>
<path d="M254 214.6h2.5l-1.2 2.6zM254 217.2h2.5M257.8 214.6h2.5l-1.2 2.6zM257.8 217.2h2.5M261.6 214.6h2.6l-1.3 2.6zM261.6 217.2h2.6M265.4 214.6h2.6l-1.3 2.6zM265.4 217.2h2.6M273 214.6h2.6l-1.3 2.6zM276.9 214.6h2.5l-1.3 2.6zM280.7 214.6h2.5l-1.3 2.6zM280.7 217.2h2.5"/>
<path d="M147.3 223.5h5.1v7.6h-5.1zM242.6 224.8h2.5l-1.3 2.5zM242.6 227.3h2.5M246.4 224.8h2.5l-1.3 2.5zM246.4 227.3h2.5M265.4 224.8h2.6l-1.3 2.5zM265.4 227.3h2.6M269.2 224.8h2.6l-1.3 2.5zM269.2 227.3h2.6M273 224.8h2.6l-1.3 2.5zM276.9 224.8h2.5l-1.3 2.5zM213.4 255.3h5l1.3 1.2v5.1l-1.3 1.3h-5z"/>
</g>
<path d="M107.2 175.5h.5v4.6h-.5z" fill="#4c566a" stroke="#4c566a" stroke-width=".18"/>
<path d="M340.4 91.4h45.7v17.8h-45.7z" fill="#e5e9f0" stroke="#e5e9f0" stroke-width=".18"/>
<g fill="#434c5e">
<path d="M376.4 107.7h.2v.7h.4v-.7h.1v.7h.5v-.8h.1v1h-1.3z"/>
<path d="M376.1 107.6h.1v1.1z"/>
</g>
<g fill="none" stroke="#4c566a" stroke-width=".18">
<path d="M344.2 87.6v3.8M346.7 87.6v3.8M349.2 87.6v3.8M351.8 87.6v3.8M354.3 87.6v3.8M356.9 87.6v3.8M359.4 87.6v3.8M361.9 87.6v3.8M364.5 87.6v3.8M367 87.6v3.8M369.6 87.6v3.8M372.1 87.6v3.8"/>
<path d="M374.6 87.6v3.8M377.2 87.6v3.8M379.7 87.6v3.8M382.3 87.6v3.8M336.5 100.3h3.9"/>
</g>
<path d="M399.5 107.2h.3l.4 1.1 .4-1.1h.2v1.3h-.2v-1.1l-.3 1.1h-.2l-.4-1.1v1.1h-.2z" fill="#5e81ac"/>
<g fill="none" stroke="#4c566a" stroke-width=".18">
<path d="M233.7 95.3v-1.3l-1.3 1.3 1.3 1.2v-1.2h1.2M236.2 95.3h1.3M242.6 97.8v1.9M242.6 95.3h1.2M233.7 108v-1.3l-1.3 1.3 1.3 1.2v-1.2h1.2M236.7 106.4v-.7h.8h-.8l1.6 1.5M237.5 108h7.6M238 106.4v-.7h.8h-.8l1.5 1.5M242.6 103.5v1.9M330.2 128.3v1.2h1.3l-1.3 1.3-1.3-1.3h1.3M331.5 137.2l1.2 .7M331.5 137.2h2.5"/>
<path d="M332.7 136.4l-1.2 .8M349.2 128.3v1.2h1.3l-1.3 1.3-1.2-1.3h1.2M109.2 221h5.1M109.2 228.6h5.1M109.2 223.5h5.1M109.2 232.4h5.1M109.2 234.9h5.1M129.5 221h5.1M129.5 228.6h5.1M129.5 232.4h5.1M129.5 234.9h5.1M129.5 226.1h5.1"/>
<path d="M129.5 238.8h5.1"/>
</g>
<path d="M240 100.5h5.1v2.2h-5.1z" fill="none" stroke="#4c566a" stroke-width=".3"/>
<path d="M241.3 99.7h2.5M241.3 103.5h2.5" fill="none" stroke="#4c566a" stroke-width=".51"/>
<path d="M237.5 94.2h5.1v2.1h-5.1zM240 108l2.6-1.3v2.5zM240 106.7v2.5M114.3 218.4h15.2v22.9h-15.2z" fill="none" stroke="#4c566a" stroke-width=".25"/>
<path d="M114.3 218.4h15.2v22.9h-15.2z" fill="#e5e9f0" stroke="#e5e9f0" stroke-width=".18"/>
<path d="M126.6 216.4h.9v.1h-.7v.4h.7v.2h-.7v.4h.8v.2h-1z" fill="#5e81ac"/>
<g fill="none" stroke="#4c566a" stroke-width=".18">
<path d="M33 35.6h5.1M33 38.1h5.1M44.4 35.6h5.1M44.4 38.1h5.1M58.4 35.6h2.6M59.7 34.8l1.3 .8M61 35.6l-1.3 .7M33 45.7h5.1M33 48.3h5.1M33 50.8h5.1M33 53.3h5.1M33 55.9h5.1"/>
<path d="M33 58.4h5.1M33 40.6h5.1M33 43.2h5.1M44.4 45.7h5.1M44.4 48.3h5.1M44.4 50.8h5.1M44.4 53.3h5.1M44.4 55.9h5.1M44.4 58.4h5.1M44.4 40.6h5.1M44.4 43.2h5.1M33 61h5.1"/>
<path d="M33 63.5h5.1M33 66h5.1M33 68.6h5.1M44.4 61h5.1M44.4 63.5h5.1M44.4 66h5.1M44.4 68.6h5.1M331.5 74.9l1.2 .8M331.5 74.9h2.5M332.7 74.2l-1.2 .7M342.6 79.5l2.6 2.5M346.7 77.5v1.2"/>
<path d="M365.5 79.5l2.5 2.5M369.6 77.5v1.2M342.6 81l2.6 2.6M344.4 83.6h.8M344.4 82h.8M345.2 81.3v.7M345.2 82.8v.8M346.7 83.8v1.3M365.5 81l2.5 2.6M369.6 83.8v1.3M346.7 139.7v1.3M349.2 139.7v1.3"/>
<path d="M351.8 139.7v1.3M354.3 139.7v1.3M356.9 139.7v1.3M359.4 139.7v1.3M361.9 139.7v1.3M364.5 139.7v1.3M367 139.7v1.3M369.6 139.7v1.3M372.1 139.7v1.3M374.6 139.7v1.3M377.2 139.7v1.3M379.7 139.7v1.3"/>
<path d="M342.6 143.3l2.6 2.5M342.6 141.7l2.6 2.6M344.4 145.8h.8M344.4 144.3h.8M345.2 143.5v.8M345.2 145v.8M345.2 143.3l2.5 2.5M345.2 141.7l2.5 2.6M346.7 146.1v1.2M347.7 143.3l2.6 2.5M347.7 141.7l2.6 2.6M349.2 146.1v1.2"/>
<path d="M350.3 143.3l2.5 2.5M350.3 141.7l2.5 2.6M351.8 146.1v1.2M352.8 143.3l2.5 2.5M352.8 141.7l2.5 2.6M354.3 146.1v1.2M355.3 143.3l2.6 2.5M355.3 141.7l2.6 2.6M356.9 146.1v1.2M357.9 143.3l2.5 2.5M357.9 141.7l2.5 2.6M359.4 146.1v1.2"/>
<path d="M360.4 143.3l2.6 2.5M360.4 141.7l2.6 2.6M361.9 146.1v1.2M363 143.3l2.5 2.5M363 141.7l2.5 2.6M364.5 146.1v1.2M365.5 143.3l2.5 2.5M365.5 141.7l2.5 2.6M367 146.1v1.2M368 143.3l2.6 2.5M368 141.7l2.6 2.6M369.6 146.1v1.2"/>
<path d="M370.6 143.3l2.5 2.5M370.6 141.7l2.5 2.6M372.1 146.1v1.2M373.1 143.3l2.6 2.5M373.1 141.7l2.6 2.6M374.6 146.1v1.2M375.7 143.3l2.5 2.5M375.7 141.7l2.5 2.6M377.2 146.1v1.2M379.7 146.1v1.2M71.1 177.8h2.8M72.1 179.1h1.1"/>
<path d="M72.6 178.6v1M73.9 175.5h.5v4.6h-.5zM75.9 177.8h2.8M224.8 171.5v2.7M224.8 176.3v2.8M234.9 171.5v2.7M234.9 176.3v2.8M245.1 171.5v2.7M245.1 176.3v2.8M287 179.6l-1.3 .7M325.1 162.6l1.3 .7M325.1 162.6h2.6"/>
<path d="M326.4 161.8l-1.3 .8M330.2 174v2.8M330.2 178.8v2.8M241.3 181.6v1.3h1.3l-1.3 1.3-1.3-1.3h1.3M285.7 180.3h2.6M285.7 180.3l1.3 .8M295.9 180.3h3.8M295.9 182.9h3.8M295.9 185.4h3.8M295.9 188h3.8M299.7 187.8h1.3v.3h-1.3zM299.7 185.3h1.3v.2h-1.3z"/>
<path d="M299.7 182.8h1.3v.2h-1.3zM299.7 180.2h1.3v.3h-1.3zM330.2 190.5v1.3h1.3l-1.3 1.2-1.3-1.2h1.3M349.2 190.5v1.3h1.3l-1.3 1.2-1.2-1.2h1.2M349.2 180.3v1.3M349.2 186.7v1.3M377.2 180.3v1.3M377.2 186.7v1.3M285.7 212.1v7.6M286.5 218.9l1.5 1.6v-.8v.8h-.7M286.5 217.7l1.5 1.5v-.8v.8h-.7M289.6 212.1v7.6"/>
<path d="M290.3 218.9l1.5 1.6v-.8v.8h-.7M290.3 217.7l1.5 1.5v-.8v.8h-.7M285.7 232.4v1.3h1.3l-1.3 1.2-1.2-1.2h1.2M285.7 222.2v7.7M286.5 229.1l1.5 1.5v-.7v.7h-.7M286.5 227.8l1.5 1.6v-.8v.8h-.7M289.6 222.2v7.7M290.3 229.1l1.5 1.5v-.7v.7h-.7M290.3 227.8l1.5 1.6v-.8v.8h-.7M325.1 228.6l1.3 .8M325.1 228.6h2.6M325.1 231.1l1.3 .8"/>
<path d="M325.1 231.1h2.6M326.4 227.8l-1.3 .8M326.4 230.4l-1.3 .7M330.2 228.6h2.5M330.2 231.1h2.5M332.7 227.3h12.7v5.1h-12.7zM345.4 228.6h2.6M345.4 231.1h2.6M351.8 229.9h1.3v-1.3l1.2 1.3-1.2 1.2v-1.2"/>
</g>
<g fill="none" stroke="#4c566a" stroke-width=".25">
<path d="M38.1 33h6.3v38.1h-6.3zM345.7 78.7h2v5.1h-2zM368.6 78.7h2v5.1h-2zM345.7 141h2v5.1h-2zM348.2 141h2.1v5.1h-2.1zM350.8 141h2v5.1h-2zM353.3 141h2v5.1h-2zM355.9 141h2v5.1h-2zM358.4 141h2v5.1h-2zM360.9 141h2.1v5.1h-2.1zM363.5 141h2v5.1h-2zM366 141h2v5.1h-2z"/>
<path d="M368.6 141h2v5.1h-2zM371.1 141h2v5.1h-2zM373.6 141h2.1v5.1h-2.1zM376.2 141h2v5.1h-2zM378.7 141h2v5.1h-2zM299.7 179.1h2.6v10.1h-2.6zM348.2 181.6h2.1v5.1h-2.1zM376.2 181.6h2v5.1h-2zM284.5 214.6h2.5l-1.3 2.6zM284.5 217.2h2.5M288.3 214.6h2.5l-1.2 2.6zM288.3 217.2h2.5"/>
<path d="M284.5 224.8h2.5l-1.3 2.5zM284.5 227.3h2.5M288.3 224.8h2.5l-1.2 2.5zM288.3 227.3h2.5"/>
</g>
<path d="M222.8 176h4M222.8 174.5h4M232.9 176h4.1M232.9 174.5h4.1M243.1 176h4M243.1 174.5h4M328.2 177h4M328.2 178.6h4" fill="none" stroke="#4c566a" stroke-width=".51"/>
<g fill="#e5e9f0" stroke="#e5e9f0" stroke-width=".18">
<path d="M299.7 179.1h2.6v10.1h-2.6z"/>
<path d="M332.7 227.3h12.7v5.1h-12.7z"/>
<path d="M38.1 33h6.3v38.1h-6.3z"/>
</g>
<path d="M75.4 175.5h.5v4.6h-.5z" fill="#4c566a" stroke="#4c566a" stroke-width=".18"/>
<path d="M45.5 29.8l.4-.1 .3 .2v.3l-.2 .1 .2 .1 .1 .3-.2 .3h-.4l-.3-.2v-.2h.1l.3 .3h.2l.1-.2-.1-.3h-.3v-.1l.3-.1v-.3h-.3l-.1 .2h-.2z" fill="#5e81ac"/>
<path d="M58.4 38.1h2.6M59.7 37.3l1.3 .8M61 38.1l-1.3 .8M90.2 27.9v2.6M90.2 35.6v2.5M66 177.8l1.3 .8M66 177.8h2.6M67.3 177l-1.3 .8" fill="none" stroke="#4c566a" stroke-width=".18"/>
<g fill="none" stroke="#4c566a" stroke-width="1.3">
<circle cx="90.2" cy="34.3" r="1.27"/>
<circle cx="90.2" cy="26.7" r="1.27"/>
<circle cx="97.8" cy="26.7" r="1.27"/>
<circle cx="97.8" cy="34.3" r="1.27"/>
<circle cx="105.4" cy="26.7" r="1.27"/>
<circle cx="105.4" cy="34.3" r="1.27"/>
<circle cx="113" cy="49.5" r="1.27"/>
<circle cx="120.7" cy="41.9" r="1.27"/>
</g>
<path d="M138.2 43.5l.3-.1 .3 .1v-.4h.1v1.2h-.1v-.1l-.3 .2-.3-.2-.1-.3h.2l.2 .3 .2-.1 .1-.2-.1-.3-.2-.1-.2 .1v.3h-.2z" fill="#5e81ac"/>
<g fill="none" stroke="#4c566a" stroke-width="1.3">
<circle cx="113" cy="34.3" r="1.27"/>
<circle cx="120.7" cy="34.3" r="1.27"/>
</g>
<path d="M138.3 35.9l.2-.1 .3 .1v-.5h.1v1.3h-.1v-.1l-.3 .1-.3-.1-.1-.4h.2v.3l.2 .1 .3-.3-.1-.3-.2-.1-.2 .1v.2h-.2z" fill="#5e81ac"/>
<circle cx="120.7" cy="26.7" r="1.27" fill="none" stroke="#4c566a" stroke-width="1.3"/>
<path d="M138.3 28.2h.2l.3 .1v-.5h.1v1.3h-.1v-.1l-.3 .1-.3-.1-.1-.4h.2v.3l.2 .1 .3-.3-.1-.3-.2-.1-.2 .1v.2h-.2z" fill="#5e81ac"/>
<circle cx="120.6" cy="49.5" r="1.27" fill="none" stroke="#4c566a" stroke-width="1.3"/>
<path d="M138.2 51.1l.3-.1 .3 .1v-.4h.1v1.3h-.1v-.2l-.3 .2-.3-.2-.1-.3h.2l.2 .3h.2l.1-.3-.1-.2-.2-.2-.2 .1v.3h-.2z" fill="#5e81ac"/>
<g fill="none" stroke="#4c566a" stroke-width="1.3">
<circle cx="113" cy="26.7" r="1.27"/>
<circle cx="90.2" cy="49.5" r="1.27"/>
<circle cx="90.2" cy="41.9" r="1.27"/>
<circle cx="97.8" cy="49.5" r="1.27"/>
<circle cx="97.8" cy="41.9" r="1.27"/>
<circle cx="105.4" cy="49.5" r="1.27"/>
<circle cx="105.4" cy="41.9" r="1.27"/>
<circle cx="113" cy="41.9" r="1.27"/>
</g>
<g fill="none" stroke="#4c566a" stroke-width=".18">
<path d="M90.2 43.2v2.5M90.2 50.8v2.5M58.4 69.9v1.2h1.3l-1.3 1.3-1.3-1.3h1.3M48.3 96.5v7.6M53.3 87.6l-.7 1.3M53.3 87.6v2.6M53.3 87.6l.8 1.3M58.4 99.1h5.1M35.6 110.5v2.5M35.6 119.4v1.3M35.6 110.5l-.8 1.3M35.6 110.5l.7 1.3"/>
<path d="M38.1 116.8h1.3M44.4 116.8h1.3M48.3 116.8h2.8M51.6 116.8h1.7v5.1M51.6 115.1h2.5v3.5h-2.5M53.3 111.8v3.3M53.6 116.3l.1 .2h.8l.1 .1M54.1 116.5l.4 .6h-.8zM58.4 101.6h5.1M71.1 109.2v1.3M71.1 115.6v1.2M71.1 119.4v2.8"/>
<path d="M35.6 125.7v1.3M43.2 139.7v1.3M45.7 137.2h5.4M51.6 137.2h1.7v5M51.6 135.4h2.5v3.5h-2.5M53.3 132.1v3.3M53.6 136.7l.1 .1h.8l.1 .1M54.1 136.8l.4 .6h-.8zM71.1 124.2v2.8M43.2 146.1v1.2M66.3 145h4.6v.5h-4.6zM66.8 143.8h1"/>
<path d="M67.3 143.3v1M68.6 152.4v1.3h1.2l-1.2 1.2-1.3-1.2h1.3M68.6 142.2v2.8M68.6 147.1v2.8"/>
</g>
<g fill="none" stroke="#4c566a" stroke-width=".25">
<path d="M47 99.1h2.5M48.3 99.1l1.2 2.5h-2.5zM63.5 96.5h5.1v7.6h-5.1zM39.4 115.8h5v2.1h-5zM51.1 114.9v3.8M51.6 114.6v1M51.6 116.3v1M51.6 118.1v1M70.1 110.5h2v5.1h-2zM34.5 120.7h2.1v5h-2.1zM51.1 135.3v3.8M51.6 134.9v1"/>
<path d="M51.6 136.7v1M51.6 138.4v1M42.2 141h2v5.1h-2z"/>
<circle cx="52.5" cy="116.8" r="2.79"/>
<circle cx="52.5" cy="137.2" r="2.79"/>
</g>
<g fill="#4c566a" stroke="#4c566a" stroke-width=".18">
<path d="M51.8 116.8l1-.3v.7z"/>
<path d="M66.3 146.6h4.6v.5h-4.6z"/>
<path d="M51.8 137.2l1-.4v.7z"/>
<circle cx="53.3" cy="118.6" r=".25"/>
<circle cx="53.3" cy="115.1" r=".25"/>
<circle cx="53.3" cy="138.9" r=".25"/>
<circle cx="53.3" cy="135.4" r=".25"/>
</g>
<path d="M69.1 124h4.1M69.1 122.4h4.1" fill="none" stroke="#4c566a" stroke-width=".51"/>
<path d="M64.9 137.7h.2l.5 1.2h-.2l-.2-.3h-.5l-.1 .3h-.2l.2-.5h.6l-.2-.6-.2 .6h-.2z" fill="#5e81ac"/>
<g fill="none" stroke="#4c566a" stroke-width=".18">
<path d="M68.6 137.2l-.8 1.2M68.6 137.2v2.5M68.6 137.2l.7 1.2M53.3 153.7v1.2h1.3l-1.3 1.3-1.2-1.3h1.2M81.3 177.8h1.2v-1.3l1.3 1.3-1.3 1.3v-1.3M81.3 191.8h2.5M82.5 191l1.3 .8M83.8 191.8l-1.3 .7M81.3 209.6h1.2v-1.3l1.3 1.3-1.3 1.2v-1.2M81.3 238.8h1.2v-1.3l1.3 1.3-1.3 1.2v-1.2M81.3 221h2.5M82.5 220.2l1.3 .8"/>
<path d="M82.5 228.6h5.1M82.5 226.1h5.1M83.8 221l-1.3 .7M48.3 255.3h5M48.3 252.7h5M48.3 257.8h5M68.6 255.3h5.1M68.6 252.7h5.1M68.6 257.8h5.1M82.5 255.3h2.6M83.8 254.5l1.3 .8M85.1 255.3l-1.3 .7"/>
<path d="M99.1 255.3v-1.3l-1.3 1.3 1.3 1.2v-1.2h1.2"/>
</g>
<path d="M87.6 223.5h5.1v7.6h-5.1zM53.3 250.2h15.3v10.1h-15.3z" fill="none" stroke="#4c566a" stroke-width=".25"/>
<path d="M53.3 250.2h15.3v10.1h-15.3z" fill="#e5e9f0" stroke="#e5e9f0" stroke-width=".18"/>
<path d="M70.6 248.2h.1v.8h.2v.1h-.2v.3h-.1v-.3h-.6v-.1h.6v-.5l-.4 .5h-.2z" fill="#5e81ac"/>
<path d="M53.3 218.4h15.3v22.9h-15.3z" fill="#e5e9f0" stroke="#e5e9f0" stroke-width=".18"/>
<path d="M53.3 218.4h15.3v22.9h-15.3z" fill="none" stroke="#4c566a" stroke-width=".25"/>
<path d="M48.3 221h5M48.3 228.6h5M48.3 223.5h5M48.3 232.4h5M48.3 234.9h5M68.6 221h5.1M68.6 228.6h5.1M68.6 232.4h5.1M68.6 234.9h5.1M68.6 226.1h5.1M68.6 238.8h5.1" fill="none" stroke="#4c566a" stroke-width=".18"/>
<path d="M65.7 216.4h.9v.1h-.7v.4h.6v.2h-.6v.4h.7v.2h-.9z" fill="#5e81ac"/>
<g fill="none" stroke="#4c566a" stroke-width=".18">
<path d="M35.6 177.8l1.2 .8M35.6 177.8h2.5M36.8 177l-1.2 .8M40.6 177.8h2.8M41.7 179.1h1M42.2 178.6v1M43.4 175.5h.5v4.6h-.5zM45.5 177.8h2.8M97.8 177.8h2.5M97.8 177.8l1.3 .8M99.1 177l-1.3 .8M48.3 199.4h5"/>
<path d="M48.3 191.8h5M48.3 194.3h5M68.6 196.9h5.1M68.6 199.4h5.1M68.6 191.8h5.1M82.5 196.9h5.1M82.5 199.4h5.1M48.3 203.2h5M48.3 205.7h5M68.6 203.2h5.1M68.6 205.7h5.1M68.6 209.6h5.1"/>
<path d="M38.1 255.3v-1.3l-1.3 1.3 1.3 1.2v-1.2h1.3"/>
</g>
<path d="M53.3 189.2h15.3v22.9h-15.3zM87.6 194.3h5.1v7.6h-5.1z" fill="none" stroke="#4c566a" stroke-width=".25"/>
<path d="M45 175.5h.5v4.6h-.5z" fill="#4c566a" stroke="#4c566a" stroke-width=".18"/>
<path d="M53.3 189.2h15.3v22.9h-15.3z" fill="#e5e9f0" stroke="#e5e9f0" stroke-width=".18"/>
<path d="M65.7 187.2h.9v.1h-.7v.4h.6v.2h-.6v.4h.7v.2h-.9z" fill="#5e81ac"/>
<path d="M50.8 177.8h1.3v-1.3l1.2 1.3-1.2 1.3v-1.3" fill="none" stroke="#4c566a" stroke-width=".18"/>
<path d="M218.7 192.6l.3-.1 .3 .2v.2h-.1l-.3-.2-.2 .3v.2l.3-.2 .3 .2v.4l-.2 .2h-.3l-.2-.2-.1-.2h.2l.1 .3h.2l.2-.2v-.2l-.2-.2-.5 .3z" fill="#5e81ac"/>
<path d="M25.4 25.4h43.2v53.3h-43.2zM200.7 72.4h111.7v125.7h-111.7zM315 72.4h91.4v125.7h-91.4zM25.4 81.3h59.7v83.8h-59.7zM25.4 167.6h172.7v102.9h-172.7zM200.7 199.4h111.7v47h-111.7zM200.7 247.6h39.3v22.9h-39.3z" fill="none" stroke="#5e81ac" stroke-width=".18"/>
<g fill="none" stroke="#a3be8c" stroke-width=".18">
<path d="M17.8 11.4l2.5 2.6M49.5 35.6h8.9M49.5 38.1h8.9M49.5 43.2h7.6M49.5 40.6h7.6M49.5 50.8h8.9M49.5 53.3h8.9M49.5 45.7h8.9M49.5 48.3h8.9M49.5 58.4h8.9M49.5 55.9h8.9M49.5 66h8.9v3.9"/>
<path d="M49.5 63.5h8.9M49.5 61h8.9M49.5 68.6h8.9M334 74.9h45.7v2.6M344.2 74.9v2.6M346.7 74.9v2.6M349.2 74.9v2.6M351.8 74.9v2.6M354.3 74.9v2.6M356.9 74.9v2.6M359.4 74.9v2.6M361.9 74.9v2.6"/>
<path d="M364.5 74.9v2.6M367 74.9v2.6M369.6 74.9v2.6M372.1 74.9v2.6M374.6 74.9v2.6M377.2 74.9v2.6M48.3 96.5v-2.5h10.1v5.1M53.3 90.2v3.8M143.5 99.1h2.5M219.7 97.8h-2.5v7.6h2.5M227.3 97.8h19.1v2.5h5.1M234.9 95.3h1.3"/>
<path d="M243.8 95.3h7.7M243.8 90.2h7.7M266.7 82.6v2.5M266.7 83.8h7.6M269.2 82.6v2.5M271.8 82.6v2.5M274.3 82.6v2.5M284.5 95.3h5.1M284.5 97.8h5.1M344.2 85.1v2.5M346.7 85.1v2.5M349.2 85.1v2.5"/>
<path d="M351.8 85.1v2.5M354.3 85.1v2.5M356.9 85.1v2.5M359.4 85.1v2.5M361.9 85.1v2.5M364.5 85.1v2.5M367 85.1v2.5M369.6 85.1v2.5M372.1 85.1v2.5M374.6 85.1v2.5M377.2 85.1v2.5M379.7 85.1v2.5"/>
<path d="M35.6 113v6.4M35.6 116.8h2.5M45.7 116.8h2.6M48.3 104.1v2.6h22.8v2.5M53.3 106.7v5.1M58.4 101.6v5.1M71.1 116.8v2.6M120.6 101.6h2.6M120.6 114.3h2.6M143.5 111.8h2.5M143.5 101.6h2.5M143.5 114.3h2.5"/>
<path d="M214.6 101.6h2.6M234.9 108h2.6M245.1 108h6.4M246.4 118.1h5.1M251.5 102.9h-5.1v2.5h-19.1M284.5 110.5h5.1M284.5 108h5.1M284.5 105.4h5.1M327.7 100.3h8.8M330.2 100.3v11.5M330.2 119.4v8.9M342.9 115.6h6.3"/>
<path d="M349.2 113v5.1M359.4 113v7.7M361.9 113v7.7M364.5 113v7.7M367 113v7.7M377.2 113v5.1M389.9 100.3h2.5M35.6 137.2h10.1M35.6 127v2.5h17.7M43.2 137.2v2.5M53.3 121.9v10.2M68.6 139.7v2.5"/>
<path d="M71.1 127v1.3h-17.8M223.5 137.2h10.2M223.5 124.5v2.5M223.5 134.6v5.1M243.8 130.8h7.7M243.8 133.4h7.7M243.8 135.9h7.7M243.8 128.3h7.7M246.4 123.2h5.1M246.4 120.7h5.1M284.5 123.2h8.9M284.5 125.7h8.9"/>
<path d="M334 137.2h45.7v2.5M344.2 137.2v2.5M346.7 137.2v2.5M349.2 125.7v2.6M349.2 137.2v2.5M351.8 137.2v2.5M354.3 137.2v2.5M356.9 137.2v2.5M359.4 137.2v2.5M361.9 137.2v2.5M364.5 137.2v2.5M367 137.2v2.5"/>
<path d="M369.6 137.2v2.5M372.1 137.2v2.5M374.6 137.2v2.5M377.2 125.7v2.6M377.2 137.2v2.5M43.2 147.3v2.6h10.1M53.3 142.2v11.5M68.6 149.9v2.5M223.5 149.9v2.5M246.4 143.5h5.1M344.2 147.3v2.6M346.7 147.3v2.6"/>
<path d="M349.2 147.3v2.6M351.8 147.3v2.6M354.3 147.3v2.6M356.9 147.3v2.6M359.4 147.3v2.6M361.9 147.3v2.6M364.5 147.3v2.6M367 147.3v2.6M369.6 147.3v2.6M372.1 147.3v2.6M374.6 147.3v2.6M377.2 147.3v2.6"/>
<path d="M379.7 147.3v2.6M38.1 177.8h2.5M48.3 177.8h2.5M68.6 177.8h2.5M78.7 177.8h2.6M100.3 177.8h2.6M110.5 177.8h2.5M130.8 177.8h2.5M141 177.8h2.5M223.5 160v2.6M224.8 171.5h30.5M224.8 179.1h30.5"/>
<path d="M241.3 168.9v2.6M241.3 179.1v2.5M266.7 163.8v2.6h2.5v-2.6M268 166.4v1.2M327.7 162.6h8.8M330.2 162.6v11.4M342.9 177.8h6.3M349.2 175.3v5M359.4 175.3v5M361.9 175.3v5M364.5 175.3v5M367 175.3v5"/>
<path d="M377.2 175.3v5M389.9 162.6h2.5M38.1 191.8h10.2M38.1 194.3h10.2M38.1 199.4h10.2M73.7 191.8h7.6M73.7 199.4h8.8M73.7 196.9h8.8M99.1 191.8h10.1M99.1 194.3h10.1M99.1 199.4h10.1M134.6 191.8h6.4"/>
<path d="M134.6 199.4h7.6M134.6 196.9h7.6M288.3 188h7.6M288.3 182.9h7.6M288.3 180.3h7.6M288.3 185.4h7.6M330.2 181.6v8.9M349.2 188v2.5M377.2 188v2.5M73.7 203.2h7.6M73.7 205.7h7.6M73.7 209.6h7.6"/>
<path d="M134.6 203.2h7.6M134.6 205.7h7.6M134.6 209.6h6.4M156.2 217.2h8.9M172.7 217.2h2.6M185.4 219.7h2.6M185.4 214.6h2.6M229.9 212.1h59.7M232.4 212.1v10.1h57.2M236.2 219.7h53.4M292.1 219.7v10.2M38.1 228.6h10.2"/>
<path d="M38.1 221h10.2M38.1 223.5h10.2M73.7 228.6h8.8M73.7 238.8h7.6M73.7 232.4h7.6M73.7 234.9h7.6M73.7 221h7.6M73.7 226.1h8.8M99.1 228.6h10.1M99.1 221h10.1M99.1 223.5h10.1M134.6 228.6h7.6"/>
<path d="M134.6 238.8h6.4M134.6 232.4h7.6M134.6 234.9h7.6M134.6 221h6.4M134.6 226.1h7.6M236.2 229.9h53.4M285.7 229.9v2.5M327.7 228.6h2.5M327.7 231.1h2.5M348 228.6h2.5v2.5h-2.5M350.5 229.9h1.3M39.4 252.7h8.9"/>
<path d="M39.4 255.3h8.9M39.4 257.8h8.9M73.7 252.7h8.8M73.7 255.3h8.8M73.7 257.8h8.8M100.3 252.7h8.9M100.3 255.3h8.9M100.3 257.8h8.9M134.6 252.7h8.9M134.6 255.3h8.9M134.6 257.8h8.9M226.1 255.3v2.5h-1.3"/>
<path d="M224.8 260.3h1.3v2.6"/>
</g>
<g fill="none" stroke="#81a1c1" stroke-width=".18">
<path d="M263.6 84.5l1.2 1.2M264.8 84.5l-1.2 1.2M283.9 92.1l1.2 1.2M283.9 89.6l1.2 1.2M283.9 99.7l1.2 1.2M285.1 92.1l-1.2 1.2M285.1 89.6l-1.2 1.2M285.1 99.7l-1.2 1.2M381.7 87l1.2 1.2M382.9 87l-1.2 1.2M250.9 112.4l1.2 1.2M250.9 109.9l1.2 1.2"/>
<path d="M252.1 112.4l-1.2 1.2M252.1 109.9l-1.2 1.2M283.9 117.5l1.2 1.2M283.9 102.3l1.2 1.2M285.1 117.5l-1.2 1.2M285.1 102.3l-1.2 1.2M250.9 125.1l1.2 1.2M250.9 137.8l1.2 1.2M252.1 125.1l-1.2 1.2M252.1 137.8l-1.2 1.2M283.9 127.7l1.2 1.2M283.9 120l1.2 1.3"/>
<path d="M285.1 120l-1.2 1.3M285.1 127.7l-1.2 1.2M250.9 150.5l1.2 1.2M250.9 145.4l1.2 1.3M250.9 155.6l1.2 1.2M250.9 153.1l1.2 1.2M250.9 148l1.2 1.2M250.9 140.4l1.2 1.2M252.1 150.5l-1.2 1.2M252.1 145.4l-1.2 1.3M252.1 155.6l-1.2 1.2M252.1 153.1l-1.2 1.2"/>
<path d="M252.1 148l-1.2 1.2M252.1 140.4l-1.2 1.2M381.7 149.3l1.2 1.2M382.9 149.3l-1.2 1.2M47.7 202.6l1.2 1.2M47.7 205.1l1.2 1.2M48.9 202.6l-1.2 1.2M48.9 205.1l-1.2 1.2M108.6 205.1l1.2 1.2M108.6 202.6l1.2 1.2M109.8 205.1l-1.2 1.2M109.8 202.6l-1.2 1.2"/>
<path d="M47.7 231.8l1.2 1.2M47.7 234.3l1.2 1.3M48.9 231.8l-1.2 1.2M48.9 234.3l-1.2 1.3M108.6 231.8l1.2 1.2M108.6 234.3l1.2 1.3M109.8 231.8l-1.2 1.2M109.8 234.3l-1.2 1.3"/>
</g>
<g fill="none" stroke="#4c566a" stroke-width=".18">
<path d="M236.2 212.1v2.5M236.2 217.2v2.5M240 212.1v2.5M240 217.2v2.5M243.8 212.1v2.5M243.8 217.2v2.5M247.6 212.1v2.5M247.6 217.2v2.5M251.5 212.1v2.5M251.5 217.2v2.5M255.3 212.1v2.5M255.3 217.2v2.5"/>
<path d="M259.1 212.1v2.5M259.1 217.2v2.5M262.9 212.1v2.5M262.9 217.2v2.5M266.7 212.1v2.5M266.7 217.2v2.5M270.5 212.1v2.5M270.5 217.2v2.5M274.3 212.1v2.5M274.3 217.2v2.5M278.1 212.1v2.5M278.1 217.2v2.5"/>
<path d="M281.9 212.1v2.5M281.9 217.2v2.5M236.2 222.2v2.6M236.2 227.3v2.6M240 222.2v2.6M240 227.3v2.6M243.8 222.2v2.6M243.8 227.3v2.6M247.6 222.2v2.6M247.6 227.3v2.6M251.5 222.2v2.6M251.5 227.3v2.6"/>
<path d="M255.3 222.2v2.6M255.3 227.3v2.6M259.1 222.2v2.6M259.1 227.3v2.6M262.9 222.2v2.6M262.9 227.3v2.6M266.7 222.2v2.6M266.7 227.3v2.6M270.5 222.2v2.6M270.5 227.3v2.6M274.3 222.2v2.6M274.3 227.3v2.6"/>
<path d="M278.1 222.2v2.6M278.1 227.3v2.6M281.9 222.2v2.6M281.9 227.3v2.6"/>
</g>
<g fill="#5e81ac">
<path d="M274.3 76.7h.2l.4 1.1 .4-1.1h.1l-.4 1.3h-.2z"/>
<path d="M275.7 76.8l.4-.1 .3 .2v.2l-.1 .2 .2 .1v.3l-.2 .3h-.4l-.3-.2v-.2h.2l.2 .3 .4-.2-.1-.3h-.3v-.2h.3v-.3h-.4l-.1 .2h-.2z"/>
</g>
<g fill="none" stroke="#4c566a" stroke-width=".18">
<path d="M349.2 77.5v1.2M351.8 77.5v1.2M354.3 77.5v1.2M356.9 77.5v1.2M359.4 77.5v1.2M361.9 77.5v1.2M364.5 77.5v1.2M367 77.5v1.2M219.7 97.8h2.8M224.5 97.8h2.8M349.2 83.8v1.3M351.8 83.8v1.3"/>
<path d="M354.3 83.8v1.3M356.9 83.8v1.3M359.4 83.8v1.3M361.9 83.8v1.3M364.5 83.8v1.3M367 83.8v1.3M219.7 105.4h2.8M224.5 105.4h2.8M219.7 257.8h5.1M219.7 260.3h5.1"/>
</g>
<path d="M399.5 169.4h.3l.4 1.1 .4-1.1h.2v1.3h-.2v-1.1l-.3 1.1h-.2l-.4-1.1v1.1h-.2z" fill="#5e81ac"/>
<path d="M349.2 171.5v3.8M359.4 171.5v3.8M361.9 171.5v3.8M364.5 171.5v3.8M367 171.5v3.8M377.2 171.5v3.8M386.1 162.6h3.8" fill="none" stroke="#4c566a" stroke-width=".18"/>
<g fill="#434c5e">
<path d="M376.4 169.9h.2v.7h.4v-.7h.1v.7h.5v-.7h.1v.9h-1.3z"/>
<path d="M376.1 169.8h.1v1.1z"/>
</g>
<g fill="none" stroke="#4c566a" stroke-width=".18">
<path d="M344.2 149.9v3.8M346.7 149.9v3.8M349.2 149.9v3.8M351.8 149.9v3.8M354.3 149.9v3.8M356.9 149.9v3.8M359.4 149.9v3.8M361.9 149.9v3.8M364.5 149.9v3.8M367 149.9v3.8M369.6 149.9v3.8M372.1 149.9v3.8"/>
<path d="M374.6 149.9v3.8M377.2 149.9v3.8M379.7 149.9v3.8M382.3 149.9v3.8M336.5 162.6h3.9"/>
</g>
<path d="M399.5 107.2h.3l.4 1.1 .4-1.1h.2v1.3h-.2v-1.1l-.3 1.1h-.2l-.4-1.1v1.1h-.2z" fill="#5e81ac"/>
<path d="M349.2 109.2v3.8M359.4 109.2v3.8M361.9 109.2v3.8M364.5 109.2v3.8M367 109.2v3.8M377.2 109.2v3.8M386.1 100.3h3.8" fill="none" stroke="#4c566a" stroke-width=".18"/>
<g fill="#434c5e">
<path d="M376.4 107.7h.2v.7h.4v-.7h.1v.7h.5v-.8h.1v1h-1.3z"/>
<path d="M376.1 107.6h.1v1.1z"/>
</g>
<g fill="none" stroke="#4c566a" stroke-width=".18">
<path d="M90.2 27.9v2.6M90.2 35.6v2.5M344.2 77.5v1.2M346.7 77.5v1.2M369.6 77.5v1.2M372.1 77.5v1.2M374.6 77.5v1.2M377.2 77.5v1.2M379.7 77.5v1.2M344.2 83.8v1.3M344.2 87.6v3.8M346.7 83.8v1.3"/>
<path d="M346.7 87.6v3.8M349.2 87.6v3.8M351.8 87.6v3.8M354.3 87.6v3.8M356.9 87.6v3.8M359.4 87.6v3.8M361.9 87.6v3.8M364.5 87.6v3.8M367 87.6v3.8M369.6 83.8v1.3M369.6 87.6v3.8M372.1 83.8v1.3"/>
<path d="M372.1 87.6v3.8M374.6 83.8v1.3M374.6 87.6v3.8M377.2 83.8v1.3M377.2 87.6v3.8M379.7 83.8v1.3M379.7 87.6v3.8M382.3 87.6v3.8M336.5 100.3h3.9M344.2 139.7v1.3M346.7 139.7v1.3M349.2 139.7v1.3"/>
<path d="M351.8 139.7v1.3M354.3 139.7v1.3M356.9 139.7v1.3M359.4 139.7v1.3M361.9 139.7v1.3M364.5 139.7v1.3M367 139.7v1.3M369.6 139.7v1.3M372.1 139.7v1.3M374.6 139.7v1.3M377.2 139.7v1.3M379.7 139.7v1.3"/>
<path d="M344.2 146.1v1.2M346.7 146.1v1.2M349.2 146.1v1.2M351.8 146.1v1.2M354.3 146.1v1.2M356.9 146.1v1.2M359.4 146.1v1.2M361.9 146.1v1.2M364.5 146.1v1.2M367 146.1v1.2M369.6 146.1v1.2M372.1 146.1v1.2"/>
<path d="M374.6 146.1v1.2M377.2 146.1v1.2M379.7 146.1v1.2M285.7 212.1v2.5M285.7 217.2v2.5M289.6 212.1v2.5M289.6 217.2v2.5M285.7 222.2v2.6M285.7 227.3v2.6M289.6 222.2v2.6M289.6 227.3v2.6"/>
</g>
<g fill="#5e81ac">
<path d="M138.2 43.5l.3-.1 .3 .1v-.4h.1v1.2h-.1v-.1l-.3 .2-.3-.2-.1-.3h.2l.2 .3 .2-.1 .1-.2-.1-.3-.2-.1-.2 .1v.3h-.2z"/>
<path d="M138.3 35.9l.2-.1 .3 .1v-.5h.1v1.3h-.1v-.1l-.3 .1-.3-.1-.1-.4h.2v.3l.2 .1 .3-.3-.1-.3-.2-.1-.2 .1v.2h-.2z"/>
<path d="M138.3 28.2h.2l.3 .1v-.5h.1v1.3h-.1v-.1l-.3 .1-.3-.1-.1-.4h.2v.3l.2 .1 .3-.3-.1-.3-.2-.1-.2 .1v.2h-.2z"/>
<path d="M138.2 51.1l.3-.1 .3 .1v-.4h.1v1.3h-.1v-.2l-.3 .2-.3-.2-.1-.3h.2l.2 .3h.2l.1-.3-.1-.2-.2-.2-.2 .1v.3h-.2z"/>
</g>
<path d="M90.2 43.2v2.5M90.2 50.8v2.5" fill="none" stroke="#4c566a" stroke-width=".18"/>
<g fill="#a3be8c" stroke="#a3be8c" stroke-width=".18">
<circle cx="344.2" cy="137.2" r=".46"/>
<circle cx="268" cy="166.4" r=".46"/>
<circle cx="349.2" cy="177.8" r=".46"/>
<circle cx="330.2" cy="162.6" r=".46"/>
<circle cx="350.5" cy="229.9" r=".46"/>
<circle cx="281.9" cy="222.2" r=".46"/>
<circle cx="285.7" cy="212.1" r=".46"/>
<circle cx="281.9" cy="212.1" r=".46"/>
<circle cx="278.1" cy="212.1" r=".46"/>
<circle cx="285.7" cy="222.2" r=".46"/>
<circle cx="270.5" cy="222.2" r=".46"/>
<circle cx="274.3" cy="222.2" r=".46"/>
<circle cx="266.7" cy="222.2" r=".46"/>
<circle cx="266.7" cy="83.8" r=".46"/>
<circle cx="271.8" cy="83.8" r=".46"/>
<circle cx="274.3" cy="83.8" r=".46"/>
<circle cx="278.1" cy="222.2" r=".46"/>
<circle cx="247.6" cy="222.2" r=".46"/>
<circle cx="243.8" cy="222.2" r=".46"/>
<circle cx="251.5" cy="212.1" r=".46"/>
<circle cx="251.5" cy="222.2" r=".46"/>
<circle cx="247.6" cy="212.1" r=".46"/>
<circle cx="240" cy="222.2" r=".46"/>
<circle cx="236.2" cy="222.2" r=".46"/>
<circle cx="243.8" cy="212.1" r=".46"/>
<circle cx="240" cy="212.1" r=".46"/>
<circle cx="234.9" cy="171.5" r=".46"/>
<circle cx="236.2" cy="212.1" r=".46"/>
<circle cx="234.9" cy="179.1" r=".46"/>
<circle cx="241.3" cy="179.1" r=".46"/>
<circle cx="245.1" cy="179.1" r=".46"/>
<circle cx="245.1" cy="171.5" r=".46"/>
<circle cx="242.6" cy="97.8" r=".46"/>
<circle cx="242.6" cy="105.4" r=".46"/>
<circle cx="223.5" cy="137.2" r=".46"/>
<circle cx="241.3" cy="171.5" r=".46"/>
<circle cx="232.4" cy="212.1" r=".46"/>
<circle cx="217.2" cy="101.6" r=".46"/>
<circle cx="262.9" cy="212.1" r=".46"/>
<circle cx="255.3" cy="212.1" r=".46"/>
<circle cx="259.1" cy="212.1" r=".46"/>
<circle cx="255.3" cy="222.2" r=".46"/>
<circle cx="259.1" cy="222.2" r=".46"/>
<circle cx="262.9" cy="222.2" r=".46"/>
<circle cx="266.7" cy="212.1" r=".46"/>
<circle cx="274.3" cy="212.1" r=".46"/>
<circle cx="270.5" cy="212.1" r=".46"/>
<circle cx="354.3" cy="74.9" r=".46"/>
<circle cx="359.4" cy="74.9" r=".46"/>
<circle cx="356.9" cy="74.9" r=".46"/>
<circle cx="351.8" cy="74.9" r=".46"/>
<circle cx="364.5" cy="74.9" r=".46"/>
<circle cx="361.9" cy="74.9" r=".46"/>
<circle cx="349.2" cy="74.9" r=".46"/>
<circle cx="346.7" cy="74.9" r=".46"/>
<circle cx="344.2" cy="74.9" r=".46"/>
<circle cx="330.2" cy="100.3" r=".46"/>
<circle cx="346.7" cy="137.2" r=".46"/>
<circle cx="356.9" cy="137.2" r=".46"/>
<circle cx="351.8" cy="137.2" r=".46"/>
<circle cx="354.3" cy="137.2" r=".46"/>
<circle cx="349.2" cy="137.2" r=".46"/>
<circle cx="369.6" cy="137.2" r=".46"/>
<circle cx="349.2" cy="115.6" r=".46"/>
<circle cx="372.1" cy="137.2" r=".46"/>
<circle cx="377.2" cy="137.2" r=".46"/>
<circle cx="374.6" cy="137.2" r=".46"/>
<circle cx="369.6" cy="74.9" r=".46"/>
<circle cx="372.1" cy="74.9" r=".46"/>
<circle cx="367" cy="74.9" r=".46"/>
<circle cx="377.2" cy="74.9" r=".46"/>
<circle cx="374.6" cy="74.9" r=".46"/>
<circle cx="367" cy="137.2" r=".46"/>
<circle cx="364.5" cy="137.2" r=".46"/>
<circle cx="359.4" cy="137.2" r=".46"/>
<circle cx="361.9" cy="137.2" r=".46"/>
<circle cx="58.4" cy="68.6" r=".46"/>
<circle cx="53.3" cy="94" r=".46"/>
<circle cx="53.3" cy="106.7" r=".46"/>
<circle cx="58.4" cy="106.7" r=".46"/>
<circle cx="35.6" cy="116.8" r=".46"/>
<circle cx="53.3" cy="149.9" r=".46"/>
<circle cx="53.3" cy="129.5" r=".46"/>
<circle cx="53.3" cy="128.3" r=".46"/>
<circle cx="43.2" cy="137.2" r=".46"/>
</g>
<use href="#words"/>
</svg>
